###############################################################
#  Generated by:      Cadence Innovus 21.35-s114_1
#  OS:                Linux x86_64(Host ID pc231.ee.hacettepe.edu.tr)
#  Generated on:      Wed Dec 24 11:12:51 2025
#  Design:            core_macro
#  Command:           write_lef_abstract -5.7 outputs/core_macro/core_macro.lef
###############################################################

VERSION 5.7 ;

BUSBITCHARS "[]" ;
DIVIDERCHAR "/" ;

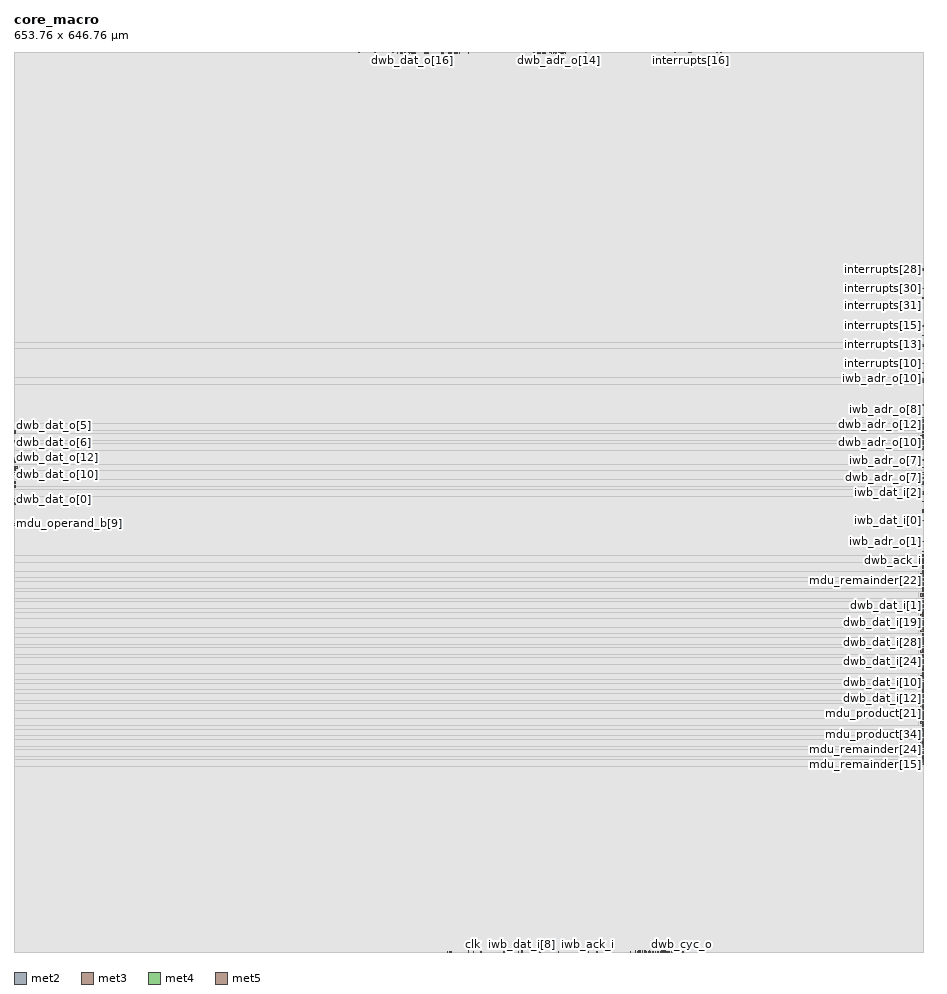
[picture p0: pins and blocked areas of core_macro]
MACRO core_macro
  CLASS BLOCK ;
  SIZE 653.760000 BY 646.760000 ;
  FOREIGN core_macro 0.000000 0.000000 ;
  ORIGIN 0 0 ;
  SYMMETRY X Y R90 ;
  PIN clk
    DIRECTION INPUT ;
    USE SIGNAL ;
    PORT
      LAYER met2 ;
        RECT 329.930000 0.000000 330.070000 0.485000 ;
    END
  END clk
  PIN rst_n
    DIRECTION INPUT ;
    USE SIGNAL ;
    PORT
      LAYER met3 ;
        RECT 652.960000 380.250000 653.760000 380.550000 ;
    END
  END rst_n
  PIN iwb_adr_o[31]
    DIRECTION OUTPUT ;
    USE SIGNAL ;
    PORT
      LAYER met2 ;
        RECT 399.050000 646.275000 399.190000 646.760000 ;
    END
  END iwb_adr_o[31]
  PIN iwb_adr_o[30]
    DIRECTION OUTPUT ;
    USE SIGNAL ;
    PORT
      LAYER met2 ;
        RECT 389.930000 646.275000 390.070000 646.760000 ;
    END
  END iwb_adr_o[30]
  PIN iwb_adr_o[29]
    DIRECTION OUTPUT ;
    USE SIGNAL ;
    PORT
      LAYER met4 ;
        RECT 391.230000 645.960000 391.530000 646.760000 ;
    END
  END iwb_adr_o[29]
  PIN iwb_adr_o[28]
    DIRECTION OUTPUT ;
    USE SIGNAL ;
    PORT
      LAYER met2 ;
        RECT 392.330000 646.275000 392.470000 646.760000 ;
    END
  END iwb_adr_o[28]
  PIN iwb_adr_o[27]
    DIRECTION OUTPUT ;
    USE SIGNAL ;
    PORT
      LAYER met2 ;
        RECT 394.250000 646.275000 394.390000 646.760000 ;
    END
  END iwb_adr_o[27]
  PIN iwb_adr_o[26]
    DIRECTION OUTPUT ;
    USE SIGNAL ;
    PORT
      LAYER met4 ;
        RECT 392.460000 645.960000 392.760000 646.760000 ;
    END
  END iwb_adr_o[26]
  PIN iwb_adr_o[25]
    DIRECTION OUTPUT ;
    USE SIGNAL ;
    PORT
      LAYER met2 ;
        RECT 393.290000 646.275000 393.430000 646.760000 ;
    END
  END iwb_adr_o[25]
  PIN iwb_adr_o[24]
    DIRECTION OUTPUT ;
    USE SIGNAL ;
    PORT
      LAYER met2 ;
        RECT 395.210000 646.275000 395.350000 646.760000 ;
    END
  END iwb_adr_o[24]
  PIN iwb_adr_o[23]
    DIRECTION OUTPUT ;
    USE SIGNAL ;
    PORT
      LAYER met4 ;
        RECT 393.690000 645.960000 393.990000 646.760000 ;
    END
  END iwb_adr_o[23]
  PIN iwb_adr_o[22]
    DIRECTION OUTPUT ;
    USE SIGNAL ;
    PORT
      LAYER met2 ;
        RECT 396.170000 646.275000 396.310000 646.760000 ;
    END
  END iwb_adr_o[22]
  PIN iwb_adr_o[21]
    DIRECTION OUTPUT ;
    USE SIGNAL ;
    PORT
      LAYER met4 ;
        RECT 396.150000 645.960000 396.450000 646.760000 ;
    END
  END iwb_adr_o[21]
  PIN iwb_adr_o[20]
    DIRECTION OUTPUT ;
    USE SIGNAL ;
    PORT
      LAYER met2 ;
        RECT 401.450000 646.275000 401.590000 646.760000 ;
    END
  END iwb_adr_o[20]
  PIN iwb_adr_o[19]
    DIRECTION OUTPUT ;
    USE SIGNAL ;
    PORT
      LAYER met2 ;
        RECT 414.410000 646.275000 414.550000 646.760000 ;
    END
  END iwb_adr_o[19]
  PIN iwb_adr_o[18]
    DIRECTION OUTPUT ;
    USE SIGNAL ;
    PORT
      LAYER met2 ;
        RECT 412.970000 646.275000 413.110000 646.760000 ;
    END
  END iwb_adr_o[18]
  PIN iwb_adr_o[17]
    DIRECTION OUTPUT ;
    USE SIGNAL ;
    PORT
      LAYER met2 ;
        RECT 411.050000 646.275000 411.190000 646.760000 ;
    END
  END iwb_adr_o[17]
  PIN iwb_adr_o[16]
    DIRECTION OUTPUT ;
    USE SIGNAL ;
    PORT
      LAYER met2 ;
        RECT 415.850000 646.275000 415.990000 646.760000 ;
    END
  END iwb_adr_o[16]
  PIN iwb_adr_o[15]
    DIRECTION OUTPUT ;
    USE SIGNAL ;
    PORT
      LAYER met2 ;
        RECT 419.690000 646.275000 419.830000 646.760000 ;
    END
  END iwb_adr_o[15]
  PIN iwb_adr_o[14]
    DIRECTION OUTPUT ;
    USE SIGNAL ;
    PORT
      LAYER met2 ;
        RECT 423.530000 646.275000 423.670000 646.760000 ;
    END
  END iwb_adr_o[14]
  PIN iwb_adr_o[13]
    DIRECTION OUTPUT ;
    USE SIGNAL ;
    PORT
      LAYER met2 ;
        RECT 424.970000 646.275000 425.110000 646.760000 ;
    END
  END iwb_adr_o[13]
  PIN iwb_adr_o[12]
    DIRECTION OUTPUT ;
    USE SIGNAL ;
    PORT
      LAYER met2 ;
        RECT 427.850000 646.275000 427.990000 646.760000 ;
    END
  END iwb_adr_o[12]
  PIN iwb_adr_o[11]
    DIRECTION OUTPUT ;
    USE SIGNAL ;
    PORT
      LAYER met3 ;
        RECT 652.960000 410.750000 653.760000 411.050000 ;
    END
  END iwb_adr_o[11]
  PIN iwb_adr_o[10]
    DIRECTION OUTPUT ;
    USE SIGNAL ;
    PORT
      LAYER met3 ;
        RECT 652.960000 411.970000 653.760000 412.270000 ;
    END
  END iwb_adr_o[10]
  PIN iwb_adr_o[9]
    DIRECTION OUTPUT ;
    USE SIGNAL ;
    PORT
      LAYER met3 ;
        RECT 652.960000 393.060000 653.760000 393.360000 ;
    END
  END iwb_adr_o[9]
  PIN iwb_adr_o[8]
    DIRECTION OUTPUT ;
    USE SIGNAL ;
    PORT
      LAYER met3 ;
        RECT 652.960000 383.910000 653.760000 384.210000 ;
    END
  END iwb_adr_o[8]
  PIN iwb_adr_o[7]
    DIRECTION OUTPUT ;
    USE SIGNAL ;
    PORT
      LAYER met3 ;
        RECT 652.960000 353.410000 653.760000 353.710000 ;
    END
  END iwb_adr_o[7]
  PIN iwb_adr_o[6]
    DIRECTION OUTPUT ;
    USE SIGNAL ;
    PORT
      LAYER met3 ;
        RECT 652.960000 287.530000 653.760000 287.830000 ;
    END
  END iwb_adr_o[6]
  PIN iwb_adr_o[5]
    DIRECTION OUTPUT ;
    USE SIGNAL ;
    PORT
      LAYER met3 ;
        RECT 652.960000 282.650000 653.760000 282.950000 ;
    END
  END iwb_adr_o[5]
  PIN iwb_adr_o[4]
    DIRECTION OUTPUT ;
    USE SIGNAL ;
    PORT
      LAYER met3 ;
        RECT 652.960000 272.890000 653.760000 273.190000 ;
    END
  END iwb_adr_o[4]
  PIN iwb_adr_o[3]
    DIRECTION OUTPUT ;
    USE SIGNAL ;
    PORT
      LAYER met3 ;
        RECT 652.960000 271.670000 653.760000 271.970000 ;
    END
  END iwb_adr_o[3]
  PIN iwb_adr_o[2]
    DIRECTION OUTPUT ;
    USE SIGNAL ;
    PORT
      LAYER met3 ;
        RECT 652.960000 275.330000 653.760000 275.630000 ;
    END
  END iwb_adr_o[2]
  PIN iwb_adr_o[1]
    DIRECTION OUTPUT ;
    USE SIGNAL ;
    PORT
      LAYER met3 ;
        RECT 652.960000 294.850000 653.760000 295.150000 ;
    END
  END iwb_adr_o[1]
  PIN iwb_adr_o[0]
    DIRECTION OUTPUT ;
    USE SIGNAL ;
    PORT
      LAYER met5 ;
        RECT 651.260000 281.390000 653.760000 282.990000 ;
    END
  END iwb_adr_o[0]
  PIN iwb_dat_i[31]
    DIRECTION INPUT ;
    USE SIGNAL ;
    PORT
      LAYER met4 ;
        RECT 378.315000 645.960000 378.615000 646.760000 ;
    END
  END iwb_dat_i[31]
  PIN iwb_dat_i[30]
    DIRECTION INPUT ;
    USE SIGNAL ;
    PORT
      LAYER met2 ;
        RECT 351.530000 646.275000 351.670000 646.760000 ;
    END
  END iwb_dat_i[30]
  PIN iwb_dat_i[29]
    DIRECTION INPUT ;
    USE SIGNAL ;
    PORT
      LAYER met2 ;
        RECT 364.490000 646.275000 364.630000 646.760000 ;
    END
  END iwb_dat_i[29]
  PIN iwb_dat_i[28]
    DIRECTION INPUT ;
    USE SIGNAL ;
    PORT
      LAYER met2 ;
        RECT 371.210000 646.275000 371.350000 646.760000 ;
    END
  END iwb_dat_i[28]
  PIN iwb_dat_i[27]
    DIRECTION INPUT ;
    USE SIGNAL ;
    PORT
      LAYER met2 ;
        RECT 354.410000 646.275000 354.550000 646.760000 ;
    END
  END iwb_dat_i[27]
  PIN iwb_dat_i[26]
    DIRECTION INPUT ;
    USE SIGNAL ;
    PORT
      LAYER met2 ;
        RECT 348.650000 646.275000 348.790000 646.760000 ;
    END
  END iwb_dat_i[26]
  PIN iwb_dat_i[25]
    DIRECTION INPUT ;
    USE SIGNAL ;
    PORT
      LAYER met2 ;
        RECT 361.130000 646.275000 361.270000 646.760000 ;
    END
  END iwb_dat_i[25]
  PIN iwb_dat_i[24]
    DIRECTION INPUT ;
    USE SIGNAL ;
    PORT
      LAYER met2 ;
        RECT 352.010000 0.000000 352.150000 0.485000 ;
    END
  END iwb_dat_i[24]
  PIN iwb_dat_i[23]
    DIRECTION INPUT ;
    USE SIGNAL ;
    PORT
      LAYER met2 ;
        RECT 357.290000 0.000000 357.430000 0.485000 ;
    END
  END iwb_dat_i[23]
  PIN iwb_dat_i[22]
    DIRECTION INPUT ;
    USE SIGNAL ;
    PORT
      LAYER met2 ;
        RECT 367.370000 646.275000 367.510000 646.760000 ;
    END
  END iwb_dat_i[22]
  PIN iwb_dat_i[21]
    DIRECTION INPUT ;
    USE SIGNAL ;
    PORT
      LAYER met2 ;
        RECT 373.610000 646.275000 373.750000 646.760000 ;
    END
  END iwb_dat_i[21]
  PIN iwb_dat_i[20]
    DIRECTION INPUT ;
    USE SIGNAL ;
    PORT
      LAYER met2 ;
        RECT 358.250000 646.275000 358.390000 646.760000 ;
    END
  END iwb_dat_i[20]
  PIN iwb_dat_i[19]
    DIRECTION INPUT ;
    USE SIGNAL ;
    PORT
      LAYER met2 ;
        RECT 377.450000 0.000000 377.590000 0.485000 ;
    END
  END iwb_dat_i[19]
  PIN iwb_dat_i[18]
    DIRECTION INPUT ;
    USE SIGNAL ;
    PORT
      LAYER met2 ;
        RECT 371.690000 0.000000 371.830000 0.485000 ;
    END
  END iwb_dat_i[18]
  PIN iwb_dat_i[17]
    DIRECTION INPUT ;
    USE SIGNAL ;
    PORT
      LAYER met2 ;
        RECT 391.370000 0.000000 391.510000 0.485000 ;
    END
  END iwb_dat_i[17]
  PIN iwb_dat_i[16]
    DIRECTION INPUT ;
    USE SIGNAL ;
    PORT
      LAYER met2 ;
        RECT 378.410000 0.000000 378.550000 0.485000 ;
    END
  END iwb_dat_i[16]
  PIN iwb_dat_i[15]
    DIRECTION INPUT ;
    USE SIGNAL ;
    PORT
      LAYER met2 ;
        RECT 364.490000 0.000000 364.630000 0.485000 ;
    END
  END iwb_dat_i[15]
  PIN iwb_dat_i[14]
    DIRECTION INPUT ;
    USE SIGNAL ;
    PORT
      LAYER met2 ;
        RECT 385.130000 646.275000 385.270000 646.760000 ;
    END
  END iwb_dat_i[14]
  PIN iwb_dat_i[13]
    DIRECTION INPUT ;
    USE SIGNAL ;
    PORT
      LAYER met4 ;
        RECT 394.920000 645.960000 395.220000 646.760000 ;
    END
  END iwb_dat_i[13]
  PIN iwb_dat_i[12]
    DIRECTION INPUT ;
    USE SIGNAL ;
    PORT
      LAYER met2 ;
        RECT 397.130000 646.275000 397.270000 646.760000 ;
    END
  END iwb_dat_i[12]
  PIN iwb_dat_i[11]
    DIRECTION INPUT ;
    USE SIGNAL ;
    PORT
      LAYER met2 ;
        RECT 362.570000 0.000000 362.710000 0.485000 ;
    END
  END iwb_dat_i[11]
  PIN iwb_dat_i[10]
    DIRECTION INPUT ;
    USE SIGNAL ;
    PORT
      LAYER met2 ;
        RECT 358.250000 0.000000 358.390000 0.485000 ;
    END
  END iwb_dat_i[10]
  PIN iwb_dat_i[9]
    DIRECTION INPUT ;
    USE SIGNAL ;
    PORT
      LAYER met2 ;
        RECT 355.850000 0.000000 355.990000 0.485000 ;
    END
  END iwb_dat_i[9]
  PIN iwb_dat_i[8]
    DIRECTION INPUT ;
    USE SIGNAL ;
    PORT
      LAYER met4 ;
        RECT 364.785000 0.000000 365.085000 0.800000 ;
    END
  END iwb_dat_i[8]
  PIN iwb_dat_i[7]
    DIRECTION INPUT ;
    USE SIGNAL ;
    PORT
      LAYER met3 ;
        RECT 652.960000 343.040000 653.760000 343.340000 ;
    END
  END iwb_dat_i[7]
  PIN iwb_dat_i[6]
    DIRECTION INPUT ;
    USE SIGNAL ;
    PORT
      LAYER met5 ;
        RECT 651.260000 328.970000 653.760000 330.570000 ;
    END
  END iwb_dat_i[6]
  PIN iwb_dat_i[5]
    DIRECTION INPUT ;
    USE SIGNAL ;
    PORT
      LAYER met3 ;
        RECT 652.960000 344.260000 653.760000 344.560000 ;
    END
  END iwb_dat_i[5]
  PIN iwb_dat_i[4]
    DIRECTION INPUT ;
    USE SIGNAL ;
    PORT
      LAYER met3 ;
        RECT 652.960000 323.520000 653.760000 323.820000 ;
    END
  END iwb_dat_i[4]
  PIN iwb_dat_i[3]
    DIRECTION INPUT ;
    USE SIGNAL ;
    PORT
      LAYER met5 ;
        RECT 651.260000 336.290000 653.760000 337.890000 ;
    END
  END iwb_dat_i[3]
  PIN iwb_dat_i[2]
    DIRECTION INPUT ;
    USE SIGNAL ;
    PORT
      LAYER met3 ;
        RECT 652.960000 335.720000 653.760000 336.020000 ;
    END
  END iwb_dat_i[2]
  PIN iwb_dat_i[1]
    DIRECTION INPUT ;
    USE SIGNAL ;
    PORT
      LAYER met3 ;
        RECT 652.960000 315.590000 653.760000 315.890000 ;
    END
  END iwb_dat_i[1]
  PIN iwb_dat_i[0]
    DIRECTION INPUT ;
    USE SIGNAL ;
    PORT
      LAYER met3 ;
        RECT 652.960000 310.100000 653.760000 310.400000 ;
    END
  END iwb_dat_i[0]
  PIN iwb_cyc_o
    DIRECTION OUTPUT ;
    USE SIGNAL ;
    PORT
      LAYER met2 ;
        RECT 418.250000 0.000000 418.390000 0.485000 ;
    END
  END iwb_cyc_o
  PIN iwb_stb_o
    DIRECTION OUTPUT ;
    USE SIGNAL ;
    PORT
      LAYER met2 ;
        RECT 419.210000 0.000000 419.350000 0.485000 ;
    END
  END iwb_stb_o
  PIN iwb_ack_i
    DIRECTION INPUT ;
    USE SIGNAL ;
    PORT
      LAYER met2 ;
        RECT 412.490000 0.000000 412.630000 0.485000 ;
    END
  END iwb_ack_i
  PIN dwb_adr_o[31]
    DIRECTION OUTPUT ;
    USE SIGNAL ;
    PORT
      LAYER met2 ;
        RECT 376.010000 646.275000 376.150000 646.760000 ;
    END
  END dwb_adr_o[31]
  PIN dwb_adr_o[30]
    DIRECTION OUTPUT ;
    USE SIGNAL ;
    PORT
      LAYER met2 ;
        RECT 378.890000 646.275000 379.030000 646.760000 ;
    END
  END dwb_adr_o[30]
  PIN dwb_adr_o[29]
    DIRECTION OUTPUT ;
    USE SIGNAL ;
    PORT
      LAYER met4 ;
        RECT 375.855000 645.960000 376.155000 646.760000 ;
    END
  END dwb_adr_o[29]
  PIN dwb_adr_o[28]
    DIRECTION OUTPUT ;
    USE SIGNAL ;
    PORT
      LAYER met2 ;
        RECT 379.850000 646.275000 379.990000 646.760000 ;
    END
  END dwb_adr_o[28]
  PIN dwb_adr_o[27]
    DIRECTION OUTPUT ;
    USE SIGNAL ;
    PORT
      LAYER met2 ;
        RECT 376.970000 646.275000 377.110000 646.760000 ;
    END
  END dwb_adr_o[27]
  PIN dwb_adr_o[26]
    DIRECTION OUTPUT ;
    USE SIGNAL ;
    PORT
      LAYER met4 ;
        RECT 379.545000 645.960000 379.845000 646.760000 ;
    END
  END dwb_adr_o[26]
  PIN dwb_adr_o[25]
    DIRECTION OUTPUT ;
    USE SIGNAL ;
    PORT
      LAYER met2 ;
        RECT 380.810000 646.275000 380.950000 646.760000 ;
    END
  END dwb_adr_o[25]
  PIN dwb_adr_o[24]
    DIRECTION OUTPUT ;
    USE SIGNAL ;
    PORT
      LAYER met2 ;
        RECT 381.770000 646.275000 381.910000 646.760000 ;
    END
  END dwb_adr_o[24]
  PIN dwb_adr_o[23]
    DIRECTION OUTPUT ;
    USE SIGNAL ;
    PORT
      LAYER met4 ;
        RECT 380.775000 645.960000 381.075000 646.760000 ;
    END
  END dwb_adr_o[23]
  PIN dwb_adr_o[22]
    DIRECTION OUTPUT ;
    USE SIGNAL ;
    PORT
      LAYER met4 ;
        RECT 377.085000 645.960000 377.385000 646.760000 ;
    END
  END dwb_adr_o[22]
  PIN dwb_adr_o[21]
    DIRECTION OUTPUT ;
    USE SIGNAL ;
    PORT
      LAYER met4 ;
        RECT 382.005000 645.960000 382.305000 646.760000 ;
    END
  END dwb_adr_o[21]
  PIN dwb_adr_o[20]
    DIRECTION OUTPUT ;
    USE SIGNAL ;
    PORT
      LAYER met2 ;
        RECT 386.090000 646.275000 386.230000 646.760000 ;
    END
  END dwb_adr_o[20]
  PIN dwb_adr_o[19]
    DIRECTION OUTPUT ;
    USE SIGNAL ;
    PORT
      LAYER met2 ;
        RECT 388.970000 646.275000 389.110000 646.760000 ;
    END
  END dwb_adr_o[19]
  PIN dwb_adr_o[18]
    DIRECTION OUTPUT ;
    USE SIGNAL ;
    PORT
      LAYER met4 ;
        RECT 389.385000 645.960000 389.685000 646.760000 ;
    END
  END dwb_adr_o[18]
  PIN dwb_adr_o[17]
    DIRECTION OUTPUT ;
    USE SIGNAL ;
    PORT
      LAYER met4 ;
        RECT 386.310000 645.960000 386.610000 646.760000 ;
    END
  END dwb_adr_o[17]
  PIN dwb_adr_o[16]
    DIRECTION OUTPUT ;
    USE SIGNAL ;
    PORT
      LAYER met2 ;
        RECT 387.050000 646.275000 387.190000 646.760000 ;
    END
  END dwb_adr_o[16]
  PIN dwb_adr_o[15]
    DIRECTION OUTPUT ;
    USE SIGNAL ;
    PORT
      LAYER met2 ;
        RECT 388.010000 646.275000 388.150000 646.760000 ;
    END
  END dwb_adr_o[15]
  PIN dwb_adr_o[14]
    DIRECTION OUTPUT ;
    USE SIGNAL ;
    PORT
      LAYER met2 ;
        RECT 391.370000 646.275000 391.510000 646.760000 ;
    END
  END dwb_adr_o[14]
  PIN dwb_adr_o[13]
    DIRECTION OUTPUT ;
    USE SIGNAL ;
    PORT
      LAYER met3 ;
        RECT 652.960000 381.470000 653.760000 381.770000 ;
    END
  END dwb_adr_o[13]
  PIN dwb_adr_o[12]
    DIRECTION OUTPUT ;
    USE SIGNAL ;
    PORT
      LAYER met3 ;
        RECT 652.960000 373.540000 653.760000 373.840000 ;
    END
  END dwb_adr_o[12]
  PIN dwb_adr_o[11]
    DIRECTION OUTPUT ;
    USE SIGNAL ;
    PORT
      LAYER met3 ;
        RECT 652.960000 382.690000 653.760000 382.990000 ;
    END
  END dwb_adr_o[11]
  PIN dwb_adr_o[10]
    DIRECTION OUTPUT ;
    USE SIGNAL ;
    PORT
      LAYER met3 ;
        RECT 652.960000 366.220000 653.760000 366.520000 ;
    END
  END dwb_adr_o[10]
  PIN dwb_adr_o[9]
    DIRECTION OUTPUT ;
    USE SIGNAL ;
    PORT
      LAYER met3 ;
        RECT 652.960000 371.710000 653.760000 372.010000 ;
    END
  END dwb_adr_o[9]
  PIN dwb_adr_o[8]
    DIRECTION OUTPUT ;
    USE SIGNAL ;
    PORT
      LAYER met4 ;
        RECT 387.540000 645.960000 387.840000 646.760000 ;
    END
  END dwb_adr_o[8]
  PIN dwb_adr_o[7]
    DIRECTION OUTPUT ;
    USE SIGNAL ;
    PORT
      LAYER met3 ;
        RECT 652.960000 340.600000 653.760000 340.900000 ;
    END
  END dwb_adr_o[7]
  PIN dwb_adr_o[6]
    DIRECTION OUTPUT ;
    USE SIGNAL ;
    PORT
      LAYER met3 ;
        RECT 652.960000 318.030000 653.760000 318.330000 ;
    END
  END dwb_adr_o[6]
  PIN dwb_adr_o[5]
    DIRECTION OUTPUT ;
    USE SIGNAL ;
    PORT
      LAYER met3 ;
        RECT 652.960000 336.940000 653.760000 337.240000 ;
    END
  END dwb_adr_o[5]
  PIN dwb_adr_o[4]
    DIRECTION OUTPUT ;
    USE SIGNAL ;
    PORT
      LAYER met3 ;
        RECT 652.960000 316.810000 653.760000 317.110000 ;
    END
  END dwb_adr_o[4]
  PIN dwb_adr_o[3]
    DIRECTION OUTPUT ;
    USE SIGNAL ;
    PORT
      LAYER met3 ;
        RECT 652.960000 329.010000 653.760000 329.310000 ;
    END
  END dwb_adr_o[3]
  PIN dwb_adr_o[2]
    DIRECTION OUTPUT ;
    USE SIGNAL ;
    PORT
      LAYER met3 ;
        RECT 652.960000 347.920000 653.760000 348.220000 ;
    END
  END dwb_adr_o[2]
  PIN dwb_adr_o[1]
    DIRECTION OUTPUT ;
    USE SIGNAL ;
    PORT
      LAYER met3 ;
        RECT 652.960000 361.340000 653.760000 361.640000 ;
    END
  END dwb_adr_o[1]
  PIN dwb_adr_o[0]
    DIRECTION OUTPUT ;
    USE SIGNAL ;
    PORT
      LAYER met3 ;
        RECT 652.960000 363.170000 653.760000 363.470000 ;
    END
  END dwb_adr_o[0]
  PIN dwb_dat_o[31]
    DIRECTION OUTPUT ;
    USE SIGNAL ;
    PORT
      LAYER met3 ;
        RECT 0.000000 348.530000 0.800000 348.830000 ;
    END
  END dwb_dat_o[31]
  PIN dwb_dat_o[30]
    DIRECTION OUTPUT ;
    USE SIGNAL ;
    PORT
      LAYER met2 ;
        RECT 243.050000 646.275000 243.190000 646.760000 ;
    END
  END dwb_dat_o[30]
  PIN dwb_dat_o[29]
    DIRECTION OUTPUT ;
    USE SIGNAL ;
    PORT
      LAYER met2 ;
        RECT 247.850000 646.275000 247.990000 646.760000 ;
    END
  END dwb_dat_o[29]
  PIN dwb_dat_o[28]
    DIRECTION OUTPUT ;
    USE SIGNAL ;
    PORT
      LAYER met2 ;
        RECT 272.330000 646.275000 272.470000 646.760000 ;
    END
  END dwb_dat_o[28]
  PIN dwb_dat_o[27]
    DIRECTION OUTPUT ;
    USE SIGNAL ;
    PORT
      LAYER met2 ;
        RECT 279.050000 646.275000 279.190000 646.760000 ;
    END
  END dwb_dat_o[27]
  PIN dwb_dat_o[26]
    DIRECTION OUTPUT ;
    USE SIGNAL ;
    PORT
      LAYER met2 ;
        RECT 282.890000 646.275000 283.030000 646.760000 ;
    END
  END dwb_dat_o[26]
  PIN dwb_dat_o[25]
    DIRECTION OUTPUT ;
    USE SIGNAL ;
    PORT
      LAYER met2 ;
        RECT 258.410000 646.275000 258.550000 646.760000 ;
    END
  END dwb_dat_o[25]
  PIN dwb_dat_o[24]
    DIRECTION OUTPUT ;
    USE SIGNAL ;
    PORT
      LAYER met2 ;
        RECT 296.330000 646.275000 296.470000 646.760000 ;
    END
  END dwb_dat_o[24]
  PIN dwb_dat_o[23]
    DIRECTION OUTPUT ;
    USE SIGNAL ;
    PORT
      LAYER met2 ;
        RECT 318.410000 646.275000 318.550000 646.760000 ;
    END
  END dwb_dat_o[23]
  PIN dwb_dat_o[22]
    DIRECTION OUTPUT ;
    USE SIGNAL ;
    PORT
      LAYER met2 ;
        RECT 322.730000 646.275000 322.870000 646.760000 ;
    END
  END dwb_dat_o[22]
  PIN dwb_dat_o[21]
    DIRECTION OUTPUT ;
    USE SIGNAL ;
    PORT
      LAYER met3 ;
        RECT 0.000000 351.580000 0.800000 351.880000 ;
    END
  END dwb_dat_o[21]
  PIN dwb_dat_o[20]
    DIRECTION OUTPUT ;
    USE SIGNAL ;
    PORT
      LAYER met2 ;
        RECT 316.490000 646.275000 316.630000 646.760000 ;
    END
  END dwb_dat_o[20]
  PIN dwb_dat_o[19]
    DIRECTION OUTPUT ;
    USE SIGNAL ;
    PORT
      LAYER met2 ;
        RECT 274.730000 646.275000 274.870000 646.760000 ;
    END
  END dwb_dat_o[19]
  PIN dwb_dat_o[18]
    DIRECTION OUTPUT ;
    USE SIGNAL ;
    PORT
      LAYER met2 ;
        RECT 311.690000 646.275000 311.830000 646.760000 ;
    END
  END dwb_dat_o[18]
  PIN dwb_dat_o[17]
    DIRECTION OUTPUT ;
    USE SIGNAL ;
    PORT
      LAYER met4 ;
        RECT 285.450000 645.960000 285.750000 646.760000 ;
    END
  END dwb_dat_o[17]
  PIN dwb_dat_o[16]
    DIRECTION OUTPUT ;
    USE SIGNAL ;
    PORT
      LAYER met2 ;
        RECT 286.250000 646.275000 286.390000 646.760000 ;
    END
  END dwb_dat_o[16]
  PIN dwb_dat_o[15]
    DIRECTION OUTPUT ;
    USE SIGNAL ;
    PORT
      LAYER met4 ;
        RECT 287.910000 645.960000 288.210000 646.760000 ;
    END
  END dwb_dat_o[15]
  PIN dwb_dat_o[14]
    DIRECTION OUTPUT ;
    USE SIGNAL ;
    PORT
      LAYER met2 ;
        RECT 336.170000 0.000000 336.310000 0.485000 ;
    END
  END dwb_dat_o[14]
  PIN dwb_dat_o[13]
    DIRECTION OUTPUT ;
    USE SIGNAL ;
    PORT
      LAYER met2 ;
        RECT 313.610000 0.000000 313.750000 0.485000 ;
    END
  END dwb_dat_o[13]
  PIN dwb_dat_o[12]
    DIRECTION OUTPUT ;
    USE SIGNAL ;
    PORT
      LAYER met3 ;
        RECT 0.000000 355.240000 0.800000 355.540000 ;
    END
  END dwb_dat_o[12]
  PIN dwb_dat_o[11]
    DIRECTION OUTPUT ;
    USE SIGNAL ;
    PORT
      LAYER met3 ;
        RECT 0.000000 346.090000 0.800000 346.390000 ;
    END
  END dwb_dat_o[11]
  PIN dwb_dat_o[10]
    DIRECTION OUTPUT ;
    USE SIGNAL ;
    PORT
      LAYER met3 ;
        RECT 0.000000 343.040000 0.800000 343.340000 ;
    END
  END dwb_dat_o[10]
  PIN dwb_dat_o[9]
    DIRECTION OUTPUT ;
    USE SIGNAL ;
    PORT
      LAYER met3 ;
        RECT 0.000000 306.440000 0.800000 306.740000 ;
    END
  END dwb_dat_o[9]
  PIN dwb_dat_o[8]
    DIRECTION OUTPUT ;
    USE SIGNAL ;
    PORT
      LAYER met2 ;
        RECT 251.210000 646.275000 251.350000 646.760000 ;
    END
  END dwb_dat_o[8]
  PIN dwb_dat_o[7]
    DIRECTION OUTPUT ;
    USE SIGNAL ;
    PORT
      LAYER met3 ;
        RECT 0.000000 336.330000 0.800000 336.630000 ;
    END
  END dwb_dat_o[7]
  PIN dwb_dat_o[6]
    DIRECTION OUTPUT ;
    USE SIGNAL ;
    PORT
      LAYER met3 ;
        RECT 0.000000 366.220000 0.800000 366.520000 ;
    END
  END dwb_dat_o[6]
  PIN dwb_dat_o[5]
    DIRECTION OUTPUT ;
    USE SIGNAL ;
    PORT
      LAYER met3 ;
        RECT 0.000000 372.930000 0.800000 373.230000 ;
    END
  END dwb_dat_o[5]
  PIN dwb_dat_o[4]
    DIRECTION OUTPUT ;
    USE SIGNAL ;
    PORT
      LAYER met2 ;
        RECT 307.370000 646.275000 307.510000 646.760000 ;
    END
  END dwb_dat_o[4]
  PIN dwb_dat_o[3]
    DIRECTION OUTPUT ;
    USE SIGNAL ;
    PORT
      LAYER met3 ;
        RECT 0.000000 333.890000 0.800000 334.190000 ;
    END
  END dwb_dat_o[3]
  PIN dwb_dat_o[2]
    DIRECTION OUTPUT ;
    USE SIGNAL ;
    PORT
      LAYER met2 ;
        RECT 311.690000 0.000000 311.830000 0.485000 ;
    END
  END dwb_dat_o[2]
  PIN dwb_dat_o[1]
    DIRECTION OUTPUT ;
    USE SIGNAL ;
    PORT
      LAYER met3 ;
        RECT 0.000000 322.910000 0.800000 323.210000 ;
    END
  END dwb_dat_o[1]
  PIN dwb_dat_o[0]
    DIRECTION OUTPUT ;
    USE SIGNAL ;
    PORT
      LAYER met3 ;
        RECT 0.000000 325.350000 0.800000 325.650000 ;
    END
  END dwb_dat_o[0]
  PIN dwb_dat_i[31]
    DIRECTION INPUT ;
    USE SIGNAL ;
    PORT
      LAYER met3 ;
        RECT 652.960000 189.930000 653.760000 190.230000 ;
    END
  END dwb_dat_i[31]
  PIN dwb_dat_i[30]
    DIRECTION INPUT ;
    USE SIGNAL ;
    PORT
      LAYER met3 ;
        RECT 652.960000 210.060000 653.760000 210.360000 ;
    END
  END dwb_dat_i[30]
  PIN dwb_dat_i[29]
    DIRECTION INPUT ;
    USE SIGNAL ;
    PORT
      LAYER met3 ;
        RECT 652.960000 256.420000 653.760000 256.720000 ;
    END
  END dwb_dat_i[29]
  PIN dwb_dat_i[28]
    DIRECTION INPUT ;
    USE SIGNAL ;
    PORT
      LAYER met3 ;
        RECT 652.960000 216.770000 653.760000 217.070000 ;
    END
  END dwb_dat_i[28]
  PIN dwb_dat_i[27]
    DIRECTION INPUT ;
    USE SIGNAL ;
    PORT
      LAYER met5 ;
        RECT 651.260000 189.890000 653.760000 191.490000 ;
    END
  END dwb_dat_i[27]
  PIN dwb_dat_i[26]
    DIRECTION INPUT ;
    USE SIGNAL ;
    PORT
      LAYER met5 ;
        RECT 651.260000 215.510000 653.760000 217.110000 ;
    END
  END dwb_dat_i[26]
  PIN dwb_dat_i[25]
    DIRECTION INPUT ;
    USE SIGNAL ;
    PORT
      LAYER met3 ;
        RECT 652.960000 223.480000 653.760000 223.780000 ;
    END
  END dwb_dat_i[25]
  PIN dwb_dat_i[24]
    DIRECTION INPUT ;
    USE SIGNAL ;
    PORT
      LAYER met3 ;
        RECT 652.960000 208.840000 653.760000 209.140000 ;
    END
  END dwb_dat_i[24]
  PIN dwb_dat_i[23]
    DIRECTION INPUT ;
    USE SIGNAL ;
    PORT
      LAYER met3 ;
        RECT 652.960000 249.710000 653.760000 250.010000 ;
    END
  END dwb_dat_i[23]
  PIN dwb_dat_i[22]
    DIRECTION INPUT ;
    USE SIGNAL ;
    PORT
      LAYER met5 ;
        RECT 651.260000 248.450000 653.760000 250.050000 ;
    END
  END dwb_dat_i[22]
  PIN dwb_dat_i[21]
    DIRECTION INPUT ;
    USE SIGNAL ;
    PORT
      LAYER met3 ;
        RECT 652.960000 196.640000 653.760000 196.940000 ;
    END
  END dwb_dat_i[21]
  PIN dwb_dat_i[20]
    DIRECTION INPUT ;
    USE SIGNAL ;
    PORT
      LAYER met3 ;
        RECT 652.960000 191.150000 653.760000 191.450000 ;
    END
  END dwb_dat_i[20]
  PIN dwb_dat_i[19]
    DIRECTION INPUT ;
    USE SIGNAL ;
    PORT
      LAYER met3 ;
        RECT 652.960000 236.900000 653.760000 237.200000 ;
    END
  END dwb_dat_i[19]
  PIN dwb_dat_i[18]
    DIRECTION INPUT ;
    USE SIGNAL ;
    PORT
      LAYER met5 ;
        RECT 651.260000 255.770000 653.760000 257.370000 ;
    END
  END dwb_dat_i[18]
  PIN dwb_dat_i[17]
    DIRECTION INPUT ;
    USE SIGNAL ;
    PORT
      LAYER met3 ;
        RECT 652.960000 257.640000 653.760000 257.940000 ;
    END
  END dwb_dat_i[17]
  PIN dwb_dat_i[16]
    DIRECTION INPUT ;
    USE SIGNAL ;
    PORT
      LAYER met5 ;
        RECT 651.260000 222.830000 653.760000 224.430000 ;
    END
  END dwb_dat_i[16]
  PIN dwb_dat_i[15]
    DIRECTION INPUT ;
    USE SIGNAL ;
    PORT
      LAYER met3 ;
        RECT 652.960000 230.190000 653.760000 230.490000 ;
    END
  END dwb_dat_i[15]
  PIN dwb_dat_i[14]
    DIRECTION INPUT ;
    USE SIGNAL ;
    PORT
      LAYER met3 ;
        RECT 652.960000 188.710000 653.760000 189.010000 ;
    END
  END dwb_dat_i[14]
  PIN dwb_dat_i[13]
    DIRECTION INPUT ;
    USE SIGNAL ;
    PORT
      LAYER met3 ;
        RECT 652.960000 192.370000 653.760000 192.670000 ;
    END
  END dwb_dat_i[13]
  PIN dwb_dat_i[12]
    DIRECTION INPUT ;
    USE SIGNAL ;
    PORT
      LAYER met3 ;
        RECT 652.960000 187.490000 653.760000 187.790000 ;
    END
  END dwb_dat_i[12]
  PIN dwb_dat_i[11]
    DIRECTION INPUT ;
    USE SIGNAL ;
    PORT
      LAYER met3 ;
        RECT 652.960000 197.860000 653.760000 198.160000 ;
    END
  END dwb_dat_i[11]
  PIN dwb_dat_i[10]
    DIRECTION INPUT ;
    USE SIGNAL ;
    PORT
      LAYER met3 ;
        RECT 652.960000 193.590000 653.760000 193.890000 ;
    END
  END dwb_dat_i[10]
  PIN dwb_dat_i[9]
    DIRECTION INPUT ;
    USE SIGNAL ;
    PORT
      LAYER met5 ;
        RECT 651.260000 197.210000 653.760000 198.810000 ;
    END
  END dwb_dat_i[9]
  PIN dwb_dat_i[8]
    DIRECTION INPUT ;
    USE SIGNAL ;
    PORT
      LAYER met3 ;
        RECT 652.960000 203.350000 653.760000 203.650000 ;
    END
  END dwb_dat_i[8]
  PIN dwb_dat_i[7]
    DIRECTION INPUT ;
    USE SIGNAL ;
    PORT
      LAYER met3 ;
        RECT 652.960000 186.270000 653.760000 186.570000 ;
    END
  END dwb_dat_i[7]
  PIN dwb_dat_i[6]
    DIRECTION INPUT ;
    USE SIGNAL ;
    PORT
      LAYER met3 ;
        RECT 652.960000 194.810000 653.760000 195.110000 ;
    END
  END dwb_dat_i[6]
  PIN dwb_dat_i[5]
    DIRECTION INPUT ;
    USE SIGNAL ;
    PORT
      LAYER met3 ;
        RECT 652.960000 185.050000 653.760000 185.350000 ;
    END
  END dwb_dat_i[5]
  PIN dwb_dat_i[4]
    DIRECTION INPUT ;
    USE SIGNAL ;
    PORT
      LAYER met3 ;
        RECT 652.960000 183.830000 653.760000 184.130000 ;
    END
  END dwb_dat_i[4]
  PIN dwb_dat_i[3]
    DIRECTION INPUT ;
    USE SIGNAL ;
    PORT
      LAYER met3 ;
        RECT 652.960000 202.130000 653.760000 202.430000 ;
    END
  END dwb_dat_i[3]
  PIN dwb_dat_i[2]
    DIRECTION INPUT ;
    USE SIGNAL ;
    PORT
      LAYER met3 ;
        RECT 652.960000 204.570000 653.760000 204.870000 ;
    END
  END dwb_dat_i[2]
  PIN dwb_dat_i[1]
    DIRECTION INPUT ;
    USE SIGNAL ;
    PORT
      LAYER met3 ;
        RECT 652.960000 243.610000 653.760000 243.910000 ;
    END
  END dwb_dat_i[1]
  PIN dwb_dat_i[0]
    DIRECTION INPUT ;
    USE SIGNAL ;
    PORT
      LAYER met3 ;
        RECT 652.960000 242.390000 653.760000 242.690000 ;
    END
  END dwb_dat_i[0]
  PIN dwb_we_o
    DIRECTION OUTPUT ;
    USE SIGNAL ;
    PORT
      LAYER met3 ;
        RECT 652.960000 365.000000 653.760000 365.300000 ;
    END
  END dwb_we_o
  PIN dwb_sel_o[3]
    DIRECTION OUTPUT ;
    USE SIGNAL ;
    PORT
      LAYER met2 ;
        RECT 326.570000 646.275000 326.710000 646.760000 ;
    END
  END dwb_sel_o[3]
  PIN dwb_sel_o[2]
    DIRECTION OUTPUT ;
    USE SIGNAL ;
    PORT
      LAYER met4 ;
        RECT 326.655000 645.960000 326.955000 646.760000 ;
    END
  END dwb_sel_o[2]
  PIN dwb_sel_o[1]
    DIRECTION OUTPUT ;
    USE SIGNAL ;
    PORT
      LAYER met2 ;
        RECT 326.570000 0.000000 326.710000 0.485000 ;
    END
  END dwb_sel_o[1]
  PIN dwb_sel_o[0]
    DIRECTION OUTPUT ;
    USE SIGNAL ;
    PORT
      LAYER met4 ;
        RECT 326.655000 0.000000 326.955000 0.800000 ;
    END
  END dwb_sel_o[0]
  PIN dwb_cyc_o
    DIRECTION OUTPUT ;
    USE SIGNAL ;
    PORT
      LAYER met2 ;
        RECT 480.170000 0.000000 480.310000 0.485000 ;
    END
  END dwb_cyc_o
  PIN dwb_stb_o
    DIRECTION OUTPUT ;
    USE SIGNAL ;
    PORT
      LAYER met2 ;
        RECT 481.130000 0.000000 481.270000 0.485000 ;
    END
  END dwb_stb_o
  PIN dwb_ack_i
    DIRECTION INPUT ;
    USE SIGNAL ;
    PORT
      LAYER met3 ;
        RECT 652.960000 281.430000 653.760000 281.730000 ;
    END
  END dwb_ack_i
  PIN dwb_err_i
    DIRECTION INPUT ;
    USE SIGNAL ;
    PORT
      LAYER met3 ;
        RECT 652.960000 367.440000 653.760000 367.740000 ;
    END
  END dwb_err_i
  PIN mdu_start
    DIRECTION OUTPUT ;
    USE SIGNAL ;
    PORT
      LAYER met3 ;
        RECT 652.960000 283.870000 653.760000 284.170000 ;
    END
  END mdu_start
  PIN mdu_ack
    DIRECTION OUTPUT ;
    USE SIGNAL ;
    PORT
      LAYER met5 ;
        RECT 651.260000 134.990000 653.760000 136.590000 ;
    END
  END mdu_ack
  PIN mdu_funct3[2]
    DIRECTION OUTPUT ;
    USE SIGNAL ;
    PORT
      LAYER met3 ;
        RECT 652.960000 228.360000 653.760000 228.660000 ;
    END
  END mdu_funct3[2]
  PIN mdu_funct3[1]
    DIRECTION OUTPUT ;
    USE SIGNAL ;
    PORT
      LAYER met3 ;
        RECT 652.960000 232.020000 653.760000 232.320000 ;
    END
  END mdu_funct3[1]
  PIN mdu_funct3[0]
    DIRECTION OUTPUT ;
    USE SIGNAL ;
    PORT
      LAYER met5 ;
        RECT 651.260000 230.150000 653.760000 231.750000 ;
    END
  END mdu_funct3[0]
  PIN mdu_operand_a[31]
    DIRECTION OUTPUT ;
    USE SIGNAL ;
    PORT
      LAYER met4 ;
        RECT 275.610000 645.960000 275.910000 646.760000 ;
    END
  END mdu_operand_a[31]
  PIN mdu_operand_a[30]
    DIRECTION OUTPUT ;
    USE SIGNAL ;
    PORT
      LAYER met2 ;
        RECT 289.610000 646.275000 289.750000 646.760000 ;
    END
  END mdu_operand_a[30]
  PIN mdu_operand_a[29]
    DIRECTION OUTPUT ;
    USE SIGNAL ;
    PORT
      LAYER met2 ;
        RECT 287.210000 646.275000 287.350000 646.760000 ;
    END
  END mdu_operand_a[29]
  PIN mdu_operand_a[28]
    DIRECTION OUTPUT ;
    USE SIGNAL ;
    PORT
      LAYER met4 ;
        RECT 296.520000 645.960000 296.820000 646.760000 ;
    END
  END mdu_operand_a[28]
  PIN mdu_operand_a[27]
    DIRECTION OUTPUT ;
    USE SIGNAL ;
    PORT
      LAYER met2 ;
        RECT 292.970000 646.275000 293.110000 646.760000 ;
    END
  END mdu_operand_a[27]
  PIN mdu_operand_a[26]
    DIRECTION OUTPUT ;
    USE SIGNAL ;
    PORT
      LAYER met2 ;
        RECT 304.010000 646.275000 304.150000 646.760000 ;
    END
  END mdu_operand_a[26]
  PIN mdu_operand_a[25]
    DIRECTION OUTPUT ;
    USE SIGNAL ;
    PORT
      LAYER met2 ;
        RECT 302.570000 646.275000 302.710000 646.760000 ;
    END
  END mdu_operand_a[25]
  PIN mdu_operand_a[24]
    DIRECTION OUTPUT ;
    USE SIGNAL ;
    PORT
      LAYER met4 ;
        RECT 306.975000 645.960000 307.275000 646.760000 ;
    END
  END mdu_operand_a[24]
  PIN mdu_operand_a[23]
    DIRECTION OUTPUT ;
    USE SIGNAL ;
    PORT
      LAYER met2 ;
        RECT 313.130000 646.275000 313.270000 646.760000 ;
    END
  END mdu_operand_a[23]
  PIN mdu_operand_a[22]
    DIRECTION OUTPUT ;
    USE SIGNAL ;
    PORT
      LAYER met4 ;
        RECT 316.200000 645.960000 316.500000 646.760000 ;
    END
  END mdu_operand_a[22]
  PIN mdu_operand_a[21]
    DIRECTION OUTPUT ;
    USE SIGNAL ;
    PORT
      LAYER met2 ;
        RECT 314.570000 646.275000 314.710000 646.760000 ;
    END
  END mdu_operand_a[21]
  PIN mdu_operand_a[20]
    DIRECTION OUTPUT ;
    USE SIGNAL ;
    PORT
      LAYER met4 ;
        RECT 314.355000 645.960000 314.655000 646.760000 ;
    END
  END mdu_operand_a[20]
  PIN mdu_operand_a[19]
    DIRECTION OUTPUT ;
    USE SIGNAL ;
    PORT
      LAYER met4 ;
        RECT 313.125000 645.960000 313.425000 646.760000 ;
    END
  END mdu_operand_a[19]
  PIN mdu_operand_a[18]
    DIRECTION OUTPUT ;
    USE SIGNAL ;
    PORT
      LAYER met4 ;
        RECT 317.430000 645.960000 317.730000 646.760000 ;
    END
  END mdu_operand_a[18]
  PIN mdu_operand_a[17]
    DIRECTION OUTPUT ;
    USE SIGNAL ;
    PORT
      LAYER met4 ;
        RECT 311.895000 645.960000 312.195000 646.760000 ;
    END
  END mdu_operand_a[17]
  PIN mdu_operand_a[16]
    DIRECTION OUTPUT ;
    USE SIGNAL ;
    PORT
      LAYER met2 ;
        RECT 315.530000 646.275000 315.670000 646.760000 ;
    END
  END mdu_operand_a[16]
  PIN mdu_operand_a[15]
    DIRECTION OUTPUT ;
    USE SIGNAL ;
    PORT
      LAYER met4 ;
        RECT 318.660000 645.960000 318.960000 646.760000 ;
    END
  END mdu_operand_a[15]
  PIN mdu_operand_a[14]
    DIRECTION OUTPUT ;
    USE SIGNAL ;
    PORT
      LAYER met4 ;
        RECT 319.890000 645.960000 320.190000 646.760000 ;
    END
  END mdu_operand_a[14]
  PIN mdu_operand_a[13]
    DIRECTION OUTPUT ;
    USE SIGNAL ;
    PORT
      LAYER met2 ;
        RECT 320.330000 646.275000 320.470000 646.760000 ;
    END
  END mdu_operand_a[13]
  PIN mdu_operand_a[12]
    DIRECTION OUTPUT ;
    USE SIGNAL ;
    PORT
      LAYER met4 ;
        RECT 308.205000 645.960000 308.505000 646.760000 ;
    END
  END mdu_operand_a[12]
  PIN mdu_operand_a[11]
    DIRECTION OUTPUT ;
    USE SIGNAL ;
    PORT
      LAYER met2 ;
        RECT 309.290000 646.275000 309.430000 646.760000 ;
    END
  END mdu_operand_a[11]
  PIN mdu_operand_a[10]
    DIRECTION OUTPUT ;
    USE SIGNAL ;
    PORT
      LAYER met2 ;
        RECT 306.410000 646.275000 306.550000 646.760000 ;
    END
  END mdu_operand_a[10]
  PIN mdu_operand_a[9]
    DIRECTION OUTPUT ;
    USE SIGNAL ;
    PORT
      LAYER met4 ;
        RECT 297.750000 645.960000 298.050000 646.760000 ;
    END
  END mdu_operand_a[9]
  PIN mdu_operand_a[8]
    DIRECTION OUTPUT ;
    USE SIGNAL ;
    PORT
      LAYER met2 ;
        RECT 295.370000 646.275000 295.510000 646.760000 ;
    END
  END mdu_operand_a[8]
  PIN mdu_operand_a[7]
    DIRECTION OUTPUT ;
    USE SIGNAL ;
    PORT
      LAYER met4 ;
        RECT 280.530000 645.960000 280.830000 646.760000 ;
    END
  END mdu_operand_a[7]
  PIN mdu_operand_a[6]
    DIRECTION OUTPUT ;
    USE SIGNAL ;
    PORT
      LAYER met4 ;
        RECT 295.290000 645.960000 295.590000 646.760000 ;
    END
  END mdu_operand_a[6]
  PIN mdu_operand_a[5]
    DIRECTION OUTPUT ;
    USE SIGNAL ;
    PORT
      LAYER met2 ;
        RECT 280.970000 646.275000 281.110000 646.760000 ;
    END
  END mdu_operand_a[5]
  PIN mdu_operand_a[4]
    DIRECTION OUTPUT ;
    USE SIGNAL ;
    PORT
      LAYER met2 ;
        RECT 278.090000 646.275000 278.230000 646.760000 ;
    END
  END mdu_operand_a[4]
  PIN mdu_operand_a[3]
    DIRECTION OUTPUT ;
    USE SIGNAL ;
    PORT
      LAYER met4 ;
        RECT 277.455000 645.960000 277.755000 646.760000 ;
    END
  END mdu_operand_a[3]
  PIN mdu_operand_a[2]
    DIRECTION OUTPUT ;
    USE SIGNAL ;
    PORT
      LAYER met4 ;
        RECT 278.685000 645.960000 278.985000 646.760000 ;
    END
  END mdu_operand_a[2]
  PIN mdu_operand_a[1]
    DIRECTION OUTPUT ;
    USE SIGNAL ;
    PORT
      LAYER met2 ;
        RECT 281.930000 646.275000 282.070000 646.760000 ;
    END
  END mdu_operand_a[1]
  PIN mdu_operand_a[0]
    DIRECTION OUTPUT ;
    USE SIGNAL ;
    PORT
      LAYER met2 ;
        RECT 300.170000 646.275000 300.310000 646.760000 ;
    END
  END mdu_operand_a[0]
  PIN mdu_operand_b[31]
    DIRECTION OUTPUT ;
    USE SIGNAL ;
    PORT
      LAYER met3 ;
        RECT 0.000000 347.310000 0.800000 347.610000 ;
    END
  END mdu_operand_b[31]
  PIN mdu_operand_b[30]
    DIRECTION OUTPUT ;
    USE SIGNAL ;
    PORT
      LAYER met2 ;
        RECT 244.010000 646.275000 244.150000 646.760000 ;
    END
  END mdu_operand_b[30]
  PIN mdu_operand_b[29]
    DIRECTION OUTPUT ;
    USE SIGNAL ;
    PORT
      LAYER met2 ;
        RECT 248.810000 646.275000 248.950000 646.760000 ;
    END
  END mdu_operand_b[29]
  PIN mdu_operand_b[28]
    DIRECTION OUTPUT ;
    USE SIGNAL ;
    PORT
      LAYER met2 ;
        RECT 271.370000 646.275000 271.510000 646.760000 ;
    END
  END mdu_operand_b[28]
  PIN mdu_operand_b[27]
    DIRECTION OUTPUT ;
    USE SIGNAL ;
    PORT
      LAYER met2 ;
        RECT 280.010000 646.275000 280.150000 646.760000 ;
    END
  END mdu_operand_b[27]
  PIN mdu_operand_b[26]
    DIRECTION OUTPUT ;
    USE SIGNAL ;
    PORT
      LAYER met2 ;
        RECT 283.850000 646.275000 283.990000 646.760000 ;
    END
  END mdu_operand_b[26]
  PIN mdu_operand_b[25]
    DIRECTION OUTPUT ;
    USE SIGNAL ;
    PORT
      LAYER met2 ;
        RECT 259.370000 646.275000 259.510000 646.760000 ;
    END
  END mdu_operand_b[25]
  PIN mdu_operand_b[24]
    DIRECTION OUTPUT ;
    USE SIGNAL ;
    PORT
      LAYER met2 ;
        RECT 297.290000 646.275000 297.430000 646.760000 ;
    END
  END mdu_operand_b[24]
  PIN mdu_operand_b[23]
    DIRECTION OUTPUT ;
    USE SIGNAL ;
    PORT
      LAYER met2 ;
        RECT 319.370000 646.275000 319.510000 646.760000 ;
    END
  END mdu_operand_b[23]
  PIN mdu_operand_b[22]
    DIRECTION OUTPUT ;
    USE SIGNAL ;
    PORT
      LAYER met2 ;
        RECT 321.770000 646.275000 321.910000 646.760000 ;
    END
  END mdu_operand_b[22]
  PIN mdu_operand_b[21]
    DIRECTION OUTPUT ;
    USE SIGNAL ;
    PORT
      LAYER met3 ;
        RECT 0.000000 352.800000 0.800000 353.100000 ;
    END
  END mdu_operand_b[21]
  PIN mdu_operand_b[20]
    DIRECTION OUTPUT ;
    USE SIGNAL ;
    PORT
      LAYER met2 ;
        RECT 317.450000 646.275000 317.590000 646.760000 ;
    END
  END mdu_operand_b[20]
  PIN mdu_operand_b[19]
    DIRECTION OUTPUT ;
    USE SIGNAL ;
    PORT
      LAYER met2 ;
        RECT 275.690000 646.275000 275.830000 646.760000 ;
    END
  END mdu_operand_b[19]
  PIN mdu_operand_b[18]
    DIRECTION OUTPUT ;
    USE SIGNAL ;
    PORT
      LAYER met2 ;
        RECT 310.730000 646.275000 310.870000 646.760000 ;
    END
  END mdu_operand_b[18]
  PIN mdu_operand_b[17]
    DIRECTION OUTPUT ;
    USE SIGNAL ;
    PORT
      LAYER met4 ;
        RECT 284.220000 645.960000 284.520000 646.760000 ;
    END
  END mdu_operand_b[17]
  PIN mdu_operand_b[16]
    DIRECTION OUTPUT ;
    USE SIGNAL ;
    PORT
      LAYER met2 ;
        RECT 285.290000 646.275000 285.430000 646.760000 ;
    END
  END mdu_operand_b[16]
  PIN mdu_operand_b[15]
    DIRECTION OUTPUT ;
    USE SIGNAL ;
    PORT
      LAYER met4 ;
        RECT 286.680000 645.960000 286.980000 646.760000 ;
    END
  END mdu_operand_b[15]
  PIN mdu_operand_b[14]
    DIRECTION OUTPUT ;
    USE SIGNAL ;
    PORT
      LAYER met2 ;
        RECT 335.210000 0.000000 335.350000 0.485000 ;
    END
  END mdu_operand_b[14]
  PIN mdu_operand_b[13]
    DIRECTION OUTPUT ;
    USE SIGNAL ;
    PORT
      LAYER met2 ;
        RECT 314.570000 0.000000 314.710000 0.485000 ;
    END
  END mdu_operand_b[13]
  PIN mdu_operand_b[12]
    DIRECTION OUTPUT ;
    USE SIGNAL ;
    PORT
      LAYER met3 ;
        RECT 0.000000 354.020000 0.800000 354.320000 ;
    END
  END mdu_operand_b[12]
  PIN mdu_operand_b[11]
    DIRECTION OUTPUT ;
    USE SIGNAL ;
    PORT
      LAYER met5 ;
        RECT 0.000000 347.270000 2.500000 348.870000 ;
    END
  END mdu_operand_b[11]
  PIN mdu_operand_b[10]
    DIRECTION OUTPUT ;
    USE SIGNAL ;
    PORT
      LAYER met3 ;
        RECT 0.000000 344.260000 0.800000 344.560000 ;
    END
  END mdu_operand_b[10]
  PIN mdu_operand_b[9]
    DIRECTION OUTPUT ;
    USE SIGNAL ;
    PORT
      LAYER met3 ;
        RECT 0.000000 307.660000 0.800000 307.960000 ;
    END
  END mdu_operand_b[9]
  PIN mdu_operand_b[8]
    DIRECTION OUTPUT ;
    USE SIGNAL ;
    PORT
      LAYER met2 ;
        RECT 250.250000 646.275000 250.390000 646.760000 ;
    END
  END mdu_operand_b[8]
  PIN mdu_operand_b[7]
    DIRECTION OUTPUT ;
    USE SIGNAL ;
    PORT
      LAYER met3 ;
        RECT 0.000000 337.550000 0.800000 337.850000 ;
    END
  END mdu_operand_b[7]
  PIN mdu_operand_b[6]
    DIRECTION OUTPUT ;
    USE SIGNAL ;
    PORT
      LAYER met3 ;
        RECT 0.000000 367.440000 0.800000 367.740000 ;
    END
  END mdu_operand_b[6]
  PIN mdu_operand_b[5]
    DIRECTION OUTPUT ;
    USE SIGNAL ;
    PORT
      LAYER met3 ;
        RECT 0.000000 374.150000 0.800000 374.450000 ;
    END
  END mdu_operand_b[5]
  PIN mdu_operand_b[4]
    DIRECTION OUTPUT ;
    USE SIGNAL ;
    PORT
      LAYER met2 ;
        RECT 308.330000 646.275000 308.470000 646.760000 ;
    END
  END mdu_operand_b[4]
  PIN mdu_operand_b[3]
    DIRECTION OUTPUT ;
    USE SIGNAL ;
    PORT
      LAYER met3 ;
        RECT 0.000000 335.110000 0.800000 335.410000 ;
    END
  END mdu_operand_b[3]
  PIN mdu_operand_b[2]
    DIRECTION OUTPUT ;
    USE SIGNAL ;
    PORT
      LAYER met2 ;
        RECT 312.650000 0.000000 312.790000 0.485000 ;
    END
  END mdu_operand_b[2]
  PIN mdu_operand_b[1]
    DIRECTION OUTPUT ;
    USE SIGNAL ;
    PORT
      LAYER met3 ;
        RECT 0.000000 321.690000 0.800000 321.990000 ;
    END
  END mdu_operand_b[1]
  PIN mdu_operand_b[0]
    DIRECTION OUTPUT ;
    USE SIGNAL ;
    PORT
      LAYER met3 ;
        RECT 0.000000 324.130000 0.800000 324.430000 ;
    END
  END mdu_operand_b[0]
  PIN mdu_busy
    DIRECTION INPUT ;
    USE SIGNAL ;
    PORT
      LAYER met2 ;
        RECT 327.530000 646.275000 327.670000 646.760000 ;
    END
  END mdu_busy
  PIN mdu_done
    DIRECTION INPUT ;
    USE SIGNAL ;
    PORT
      LAYER met3 ;
        RECT 652.960000 285.090000 653.760000 285.390000 ;
    END
  END mdu_done
  PIN mdu_product[63]
    DIRECTION INPUT ;
    USE SIGNAL ;
    PORT
      LAYER met5 ;
        RECT 651.260000 182.570000 653.760000 184.170000 ;
    END
  END mdu_product[63]
  PIN mdu_product[62]
    DIRECTION INPUT ;
    USE SIGNAL ;
    PORT
      LAYER met3 ;
        RECT 652.960000 182.610000 653.760000 182.910000 ;
    END
  END mdu_product[62]
  PIN mdu_product[61]
    DIRECTION INPUT ;
    USE SIGNAL ;
    PORT
      LAYER met3 ;
        RECT 652.960000 263.130000 653.760000 263.430000 ;
    END
  END mdu_product[61]
  PIN mdu_product[60]
    DIRECTION INPUT ;
    USE SIGNAL ;
    PORT
      LAYER met3 ;
        RECT 652.960000 150.280000 653.760000 150.580000 ;
    END
  END mdu_product[60]
  PIN mdu_product[59]
    DIRECTION INPUT ;
    USE SIGNAL ;
    PORT
      LAYER met3 ;
        RECT 652.960000 199.080000 653.760000 199.380000 ;
    END
  END mdu_product[59]
  PIN mdu_product[58]
    DIRECTION INPUT ;
    USE SIGNAL ;
    PORT
      LAYER met3 ;
        RECT 652.960000 215.550000 653.760000 215.850000 ;
    END
  END mdu_product[58]
  PIN mdu_product[57]
    DIRECTION INPUT ;
    USE SIGNAL ;
    PORT
      LAYER met3 ;
        RECT 652.960000 169.800000 653.760000 170.100000 ;
    END
  END mdu_product[57]
  PIN mdu_product[56]
    DIRECTION INPUT ;
    USE SIGNAL ;
    PORT
      LAYER met3 ;
        RECT 652.960000 143.570000 653.760000 143.870000 ;
    END
  END mdu_product[56]
  PIN mdu_product[55]
    DIRECTION INPUT ;
    USE SIGNAL ;
    PORT
      LAYER met3 ;
        RECT 652.960000 250.930000 653.760000 251.230000 ;
    END
  END mdu_product[55]
  PIN mdu_product[54]
    DIRECTION INPUT ;
    USE SIGNAL ;
    PORT
      LAYER met3 ;
        RECT 652.960000 269.840000 653.760000 270.140000 ;
    END
  END mdu_product[54]
  PIN mdu_product[53]
    DIRECTION INPUT ;
    USE SIGNAL ;
    PORT
      LAYER met3 ;
        RECT 652.960000 176.510000 653.760000 176.810000 ;
    END
  END mdu_product[53]
  PIN mdu_product[52]
    DIRECTION INPUT ;
    USE SIGNAL ;
    PORT
      LAYER met5 ;
        RECT 651.260000 175.250000 653.760000 176.850000 ;
    END
  END mdu_product[52]
  PIN mdu_product[51]
    DIRECTION INPUT ;
    USE SIGNAL ;
    PORT
      LAYER met3 ;
        RECT 652.960000 222.260000 653.760000 222.560000 ;
    END
  END mdu_product[51]
  PIN mdu_product[50]
    DIRECTION INPUT ;
    USE SIGNAL ;
    PORT
      LAYER met5 ;
        RECT 651.260000 270.410000 653.760000 272.010000 ;
    END
  END mdu_product[50]
  PIN mdu_product[49]
    DIRECTION INPUT ;
    USE SIGNAL ;
    PORT
      LAYER met3 ;
        RECT 652.960000 244.830000 653.760000 245.130000 ;
    END
  END mdu_product[49]
  PIN mdu_product[48]
    DIRECTION INPUT ;
    USE SIGNAL ;
    PORT
      LAYER met3 ;
        RECT 652.960000 163.090000 653.760000 163.390000 ;
    END
  END mdu_product[48]
  PIN mdu_product[47]
    DIRECTION INPUT ;
    USE SIGNAL ;
    PORT
      LAYER met3 ;
        RECT 652.960000 156.990000 653.760000 157.290000 ;
    END
  END mdu_product[47]
  PIN mdu_product[46]
    DIRECTION INPUT ;
    USE SIGNAL ;
    PORT
      LAYER met2 ;
        RECT 468.170000 0.000000 468.310000 0.485000 ;
    END
  END mdu_product[46]
  PIN mdu_product[45]
    DIRECTION INPUT ;
    USE SIGNAL ;
    PORT
      LAYER met2 ;
        RECT 474.410000 0.000000 474.550000 0.485000 ;
    END
  END mdu_product[45]
  PIN mdu_product[44]
    DIRECTION INPUT ;
    USE SIGNAL ;
    PORT
      LAYER met2 ;
        RECT 443.210000 0.000000 443.350000 0.485000 ;
    END
  END mdu_product[44]
  PIN mdu_product[43]
    DIRECTION INPUT ;
    USE SIGNAL ;
    PORT
      LAYER met2 ;
        RECT 446.570000 0.000000 446.710000 0.485000 ;
    END
  END mdu_product[43]
  PIN mdu_product[42]
    DIRECTION INPUT ;
    USE SIGNAL ;
    PORT
      LAYER met4 ;
        RECT 468.105000 0.000000 468.405000 0.800000 ;
    END
  END mdu_product[42]
  PIN mdu_product[41]
    DIRECTION INPUT ;
    USE SIGNAL ;
    PORT
      LAYER met2 ;
        RECT 455.690000 0.000000 455.830000 0.485000 ;
    END
  END mdu_product[41]
  PIN mdu_product[40]
    DIRECTION INPUT ;
    USE SIGNAL ;
    PORT
      LAYER met4 ;
        RECT 446.580000 0.000000 446.880000 0.800000 ;
    END
  END mdu_product[40]
  PIN mdu_product[39]
    DIRECTION INPUT ;
    USE SIGNAL ;
    PORT
      LAYER met3 ;
        RECT 652.960000 177.730000 653.760000 178.030000 ;
    END
  END mdu_product[39]
  PIN mdu_product[38]
    DIRECTION INPUT ;
    USE SIGNAL ;
    PORT
      LAYER met3 ;
        RECT 652.960000 164.310000 653.760000 164.610000 ;
    END
  END mdu_product[38]
  PIN mdu_product[37]
    DIRECTION INPUT ;
    USE SIGNAL ;
    PORT
      LAYER met2 ;
        RECT 458.570000 0.000000 458.710000 0.485000 ;
    END
  END mdu_product[37]
  PIN mdu_product[36]
    DIRECTION INPUT ;
    USE SIGNAL ;
    PORT
      LAYER met2 ;
        RECT 462.410000 0.000000 462.550000 0.485000 ;
    END
  END mdu_product[36]
  PIN mdu_product[35]
    DIRECTION INPUT ;
    USE SIGNAL ;
    PORT
      LAYER met5 ;
        RECT 651.260000 208.190000 653.760000 209.790000 ;
    END
  END mdu_product[35]
  PIN mdu_product[34]
    DIRECTION INPUT ;
    USE SIGNAL ;
    PORT
      LAYER met3 ;
        RECT 652.960000 161.870000 653.760000 162.170000 ;
    END
  END mdu_product[34]
  PIN mdu_product[33]
    DIRECTION INPUT ;
    USE SIGNAL ;
    PORT
      LAYER met3 ;
        RECT 652.960000 235.680000 653.760000 235.980000 ;
    END
  END mdu_product[33]
  PIN mdu_product[32]
    DIRECTION INPUT ;
    USE SIGNAL ;
    PORT
      LAYER met3 ;
        RECT 652.960000 227.140000 653.760000 227.440000 ;
    END
  END mdu_product[32]
  PIN mdu_product[31]
    DIRECTION INPUT ;
    USE SIGNAL ;
    PORT
      LAYER met3 ;
        RECT 652.960000 200.300000 653.760000 200.600000 ;
    END
  END mdu_product[31]
  PIN mdu_product[30]
    DIRECTION INPUT ;
    USE SIGNAL ;
    PORT
      LAYER met3 ;
        RECT 652.960000 181.390000 653.760000 181.690000 ;
    END
  END mdu_product[30]
  PIN mdu_product[29]
    DIRECTION INPUT ;
    USE SIGNAL ;
    PORT
      LAYER met3 ;
        RECT 652.960000 255.200000 653.760000 255.500000 ;
    END
  END mdu_product[29]
  PIN mdu_product[28]
    DIRECTION INPUT ;
    USE SIGNAL ;
    PORT
      LAYER met5 ;
        RECT 651.260000 164.270000 653.760000 165.870000 ;
    END
  END mdu_product[28]
  PIN mdu_product[27]
    DIRECTION INPUT ;
    USE SIGNAL ;
    PORT
      LAYER met3 ;
        RECT 652.960000 205.790000 653.760000 206.090000 ;
    END
  END mdu_product[27]
  PIN mdu_product[26]
    DIRECTION INPUT ;
    USE SIGNAL ;
    PORT
      LAYER met3 ;
        RECT 652.960000 217.990000 653.760000 218.290000 ;
    END
  END mdu_product[26]
  PIN mdu_product[25]
    DIRECTION INPUT ;
    USE SIGNAL ;
    PORT
      LAYER met3 ;
        RECT 652.960000 180.170000 653.760000 180.470000 ;
    END
  END mdu_product[25]
  PIN mdu_product[24]
    DIRECTION INPUT ;
    USE SIGNAL ;
    PORT
      LAYER met5 ;
        RECT 651.260000 149.630000 653.760000 151.230000 ;
    END
  END mdu_product[24]
  PIN mdu_product[23]
    DIRECTION INPUT ;
    USE SIGNAL ;
    PORT
      LAYER met3 ;
        RECT 652.960000 238.120000 653.760000 238.420000 ;
    END
  END mdu_product[23]
  PIN mdu_product[22]
    DIRECTION INPUT ;
    USE SIGNAL ;
    PORT
      LAYER met3 ;
        RECT 652.960000 258.860000 653.760000 259.160000 ;
    END
  END mdu_product[22]
  PIN mdu_product[21]
    DIRECTION INPUT ;
    USE SIGNAL ;
    PORT
      LAYER met3 ;
        RECT 652.960000 171.020000 653.760000 171.320000 ;
    END
  END mdu_product[21]
  PIN mdu_product[20]
    DIRECTION INPUT ;
    USE SIGNAL ;
    PORT
      LAYER met3 ;
        RECT 652.960000 175.290000 653.760000 175.590000 ;
    END
  END mdu_product[20]
  PIN mdu_product[19]
    DIRECTION INPUT ;
    USE SIGNAL ;
    PORT
      LAYER met3 ;
        RECT 652.960000 224.700000 653.760000 225.000000 ;
    END
  END mdu_product[19]
  PIN mdu_product[18]
    DIRECTION INPUT ;
    USE SIGNAL ;
    PORT
      LAYER met3 ;
        RECT 652.960000 253.980000 653.760000 254.280000 ;
    END
  END mdu_product[18]
  PIN mdu_product[17]
    DIRECTION INPUT ;
    USE SIGNAL ;
    PORT
      LAYER met5 ;
        RECT 651.260000 241.130000 653.760000 242.730000 ;
    END
  END mdu_product[17]
  PIN mdu_product[16]
    DIRECTION INPUT ;
    USE SIGNAL ;
    PORT
      LAYER met3 ;
        RECT 652.960000 178.950000 653.760000 179.250000 ;
    END
  END mdu_product[16]
  PIN mdu_product[15]
    DIRECTION INPUT ;
    USE SIGNAL ;
    PORT
      LAYER met3 ;
        RECT 652.960000 165.530000 653.760000 165.830000 ;
    END
  END mdu_product[15]
  PIN mdu_product[14]
    DIRECTION INPUT ;
    USE SIGNAL ;
    PORT
      LAYER met2 ;
        RECT 466.730000 0.000000 466.870000 0.485000 ;
    END
  END mdu_product[14]
  PIN mdu_product[13]
    DIRECTION INPUT ;
    USE SIGNAL ;
    PORT
      LAYER met2 ;
        RECT 478.250000 0.000000 478.390000 0.485000 ;
    END
  END mdu_product[13]
  PIN mdu_product[12]
    DIRECTION INPUT ;
    USE SIGNAL ;
    PORT
      LAYER met2 ;
        RECT 449.930000 0.000000 450.070000 0.485000 ;
    END
  END mdu_product[12]
  PIN mdu_product[11]
    DIRECTION INPUT ;
    USE SIGNAL ;
    PORT
      LAYER met2 ;
        RECT 453.290000 0.000000 453.430000 0.485000 ;
    END
  END mdu_product[11]
  PIN mdu_product[10]
    DIRECTION INPUT ;
    USE SIGNAL ;
    PORT
      LAYER met2 ;
        RECT 465.770000 0.000000 465.910000 0.485000 ;
    END
  END mdu_product[10]
  PIN mdu_product[9]
    DIRECTION INPUT ;
    USE SIGNAL ;
    PORT
      LAYER met2 ;
        RECT 456.650000 0.000000 456.790000 0.485000 ;
    END
  END mdu_product[9]
  PIN mdu_product[8]
    DIRECTION INPUT ;
    USE SIGNAL ;
    PORT
      LAYER met4 ;
        RECT 450.270000 0.000000 450.570000 0.800000 ;
    END
  END mdu_product[8]
  PIN mdu_product[7]
    DIRECTION INPUT ;
    USE SIGNAL ;
    PORT
      LAYER met3 ;
        RECT 652.960000 168.580000 653.760000 168.880000 ;
    END
  END mdu_product[7]
  PIN mdu_product[6]
    DIRECTION INPUT ;
    USE SIGNAL ;
    PORT
      LAYER met3 ;
        RECT 652.960000 172.240000 653.760000 172.540000 ;
    END
  END mdu_product[6]
  PIN mdu_product[5]
    DIRECTION INPUT ;
    USE SIGNAL ;
    PORT
      LAYER met4 ;
        RECT 456.420000 0.000000 456.720000 0.800000 ;
    END
  END mdu_product[5]
  PIN mdu_product[4]
    DIRECTION INPUT ;
    USE SIGNAL ;
    PORT
      LAYER met4 ;
        RECT 465.645000 0.000000 465.945000 0.800000 ;
    END
  END mdu_product[4]
  PIN mdu_product[3]
    DIRECTION INPUT ;
    USE SIGNAL ;
    PORT
      LAYER met3 ;
        RECT 652.960000 211.280000 653.760000 211.580000 ;
    END
  END mdu_product[3]
  PIN mdu_product[2]
    DIRECTION INPUT ;
    USE SIGNAL ;
    PORT
      LAYER met2 ;
        RECT 475.850000 0.000000 475.990000 0.485000 ;
    END
  END mdu_product[2]
  PIN mdu_product[1]
    DIRECTION INPUT ;
    USE SIGNAL ;
    PORT
      LAYER met3 ;
        RECT 652.960000 233.240000 653.760000 233.540000 ;
    END
  END mdu_product[1]
  PIN mdu_product[0]
    DIRECTION INPUT ;
    USE SIGNAL ;
    PORT
      LAYER met3 ;
        RECT 652.960000 225.920000 653.760000 226.220000 ;
    END
  END mdu_product[0]
  PIN mdu_quotient[31]
    DIRECTION INPUT ;
    USE SIGNAL ;
    PORT
      LAYER met3 ;
        RECT 652.960000 174.070000 653.760000 174.370000 ;
    END
  END mdu_quotient[31]
  PIN mdu_quotient[30]
    DIRECTION INPUT ;
    USE SIGNAL ;
    PORT
      LAYER met3 ;
        RECT 652.960000 207.010000 653.760000 207.310000 ;
    END
  END mdu_quotient[30]
  PIN mdu_quotient[29]
    DIRECTION INPUT ;
    USE SIGNAL ;
    PORT
      LAYER met3 ;
        RECT 652.960000 241.170000 653.760000 241.470000 ;
    END
  END mdu_quotient[29]
  PIN mdu_quotient[28]
    DIRECTION INPUT ;
    USE SIGNAL ;
    PORT
      LAYER met5 ;
        RECT 651.260000 156.950000 653.760000 158.550000 ;
    END
  END mdu_quotient[28]
  PIN mdu_quotient[27]
    DIRECTION INPUT ;
    USE SIGNAL ;
    PORT
      LAYER met3 ;
        RECT 652.960000 212.500000 653.760000 212.800000 ;
    END
  END mdu_quotient[27]
  PIN mdu_quotient[26]
    DIRECTION INPUT ;
    USE SIGNAL ;
    PORT
      LAYER met3 ;
        RECT 652.960000 219.210000 653.760000 219.510000 ;
    END
  END mdu_quotient[26]
  PIN mdu_quotient[25]
    DIRECTION INPUT ;
    USE SIGNAL ;
    PORT
      LAYER met3 ;
        RECT 652.960000 167.360000 653.760000 167.660000 ;
    END
  END mdu_quotient[25]
  PIN mdu_quotient[24]
    DIRECTION INPUT ;
    USE SIGNAL ;
    PORT
      LAYER met3 ;
        RECT 652.960000 160.650000 653.760000 160.950000 ;
    END
  END mdu_quotient[24]
  PIN mdu_quotient[23]
    DIRECTION INPUT ;
    USE SIGNAL ;
    PORT
      LAYER met3 ;
        RECT 652.960000 248.490000 653.760000 248.790000 ;
    END
  END mdu_quotient[23]
  PIN mdu_quotient[22]
    DIRECTION INPUT ;
    USE SIGNAL ;
    PORT
      LAYER met3 ;
        RECT 652.960000 246.050000 653.760000 246.350000 ;
    END
  END mdu_quotient[22]
  PIN mdu_quotient[21]
    DIRECTION INPUT ;
    USE SIGNAL ;
    PORT
      LAYER met3 ;
        RECT 652.960000 159.430000 653.760000 159.730000 ;
    END
  END mdu_quotient[21]
  PIN mdu_quotient[20]
    DIRECTION INPUT ;
    USE SIGNAL ;
    PORT
      LAYER met3 ;
        RECT 652.960000 213.720000 653.760000 214.020000 ;
    END
  END mdu_quotient[20]
  PIN mdu_quotient[19]
    DIRECTION INPUT ;
    USE SIGNAL ;
    PORT
      LAYER met3 ;
        RECT 652.960000 221.040000 653.760000 221.340000 ;
    END
  END mdu_quotient[19]
  PIN mdu_quotient[18]
    DIRECTION INPUT ;
    USE SIGNAL ;
    PORT
      LAYER met3 ;
        RECT 652.960000 252.150000 653.760000 252.450000 ;
    END
  END mdu_quotient[18]
  PIN mdu_quotient[17]
    DIRECTION INPUT ;
    USE SIGNAL ;
    PORT
      LAYER met3 ;
        RECT 652.960000 234.460000 653.760000 234.760000 ;
    END
  END mdu_quotient[17]
  PIN mdu_quotient[16]
    DIRECTION INPUT ;
    USE SIGNAL ;
    PORT
      LAYER met3 ;
        RECT 652.960000 158.210000 653.760000 158.510000 ;
    END
  END mdu_quotient[16]
  PIN mdu_quotient[15]
    DIRECTION INPUT ;
    USE SIGNAL ;
    PORT
      LAYER met3 ;
        RECT 652.960000 155.770000 653.760000 156.070000 ;
    END
  END mdu_quotient[15]
  PIN mdu_quotient[14]
    DIRECTION INPUT ;
    USE SIGNAL ;
    PORT
      LAYER met2 ;
        RECT 469.130000 0.000000 469.270000 0.485000 ;
    END
  END mdu_quotient[14]
  PIN mdu_quotient[13]
    DIRECTION INPUT ;
    USE SIGNAL ;
    PORT
      LAYER met2 ;
        RECT 472.490000 0.000000 472.630000 0.485000 ;
    END
  END mdu_quotient[13]
  PIN mdu_quotient[12]
    DIRECTION INPUT ;
    USE SIGNAL ;
    PORT
      LAYER met2 ;
        RECT 448.010000 0.000000 448.150000 0.485000 ;
    END
  END mdu_quotient[12]
  PIN mdu_quotient[11]
    DIRECTION INPUT ;
    USE SIGNAL ;
    PORT
      LAYER met2 ;
        RECT 451.370000 0.000000 451.510000 0.485000 ;
    END
  END mdu_quotient[11]
  PIN mdu_quotient[10]
    DIRECTION INPUT ;
    USE SIGNAL ;
    PORT
      LAYER met2 ;
        RECT 473.450000 0.000000 473.590000 0.485000 ;
    END
  END mdu_quotient[10]
  PIN mdu_quotient[9]
    DIRECTION INPUT ;
    USE SIGNAL ;
    PORT
      LAYER met2 ;
        RECT 457.610000 0.000000 457.750000 0.485000 ;
    END
  END mdu_quotient[9]
  PIN mdu_quotient[8]
    DIRECTION INPUT ;
    USE SIGNAL ;
    PORT
      LAYER met4 ;
        RECT 451.500000 0.000000 451.800000 0.800000 ;
    END
  END mdu_quotient[8]
  PIN mdu_quotient[7]
    DIRECTION INPUT ;
    USE SIGNAL ;
    PORT
      LAYER met3 ;
        RECT 652.960000 154.550000 653.760000 154.850000 ;
    END
  END mdu_quotient[7]
  PIN mdu_quotient[6]
    DIRECTION INPUT ;
    USE SIGNAL ;
    PORT
      LAYER met3 ;
        RECT 652.960000 153.330000 653.760000 153.630000 ;
    END
  END mdu_quotient[6]
  PIN mdu_quotient[5]
    DIRECTION INPUT ;
    USE SIGNAL ;
    PORT
      LAYER met2 ;
        RECT 459.530000 0.000000 459.670000 0.485000 ;
    END
  END mdu_quotient[5]
  PIN mdu_quotient[4]
    DIRECTION INPUT ;
    USE SIGNAL ;
    PORT
      LAYER met2 ;
        RECT 463.370000 0.000000 463.510000 0.485000 ;
    END
  END mdu_quotient[4]
  PIN mdu_quotient[3]
    DIRECTION INPUT ;
    USE SIGNAL ;
    PORT
      LAYER met3 ;
        RECT 652.960000 239.340000 653.760000 239.640000 ;
    END
  END mdu_quotient[3]
  PIN mdu_quotient[2]
    DIRECTION INPUT ;
    USE SIGNAL ;
    PORT
      LAYER met2 ;
        RECT 477.290000 0.000000 477.430000 0.485000 ;
    END
  END mdu_quotient[2]
  PIN mdu_quotient[1]
    DIRECTION INPUT ;
    USE SIGNAL ;
    PORT
      LAYER met3 ;
        RECT 652.960000 247.270000 653.760000 247.570000 ;
    END
  END mdu_quotient[1]
  PIN mdu_quotient[0]
    DIRECTION INPUT ;
    USE SIGNAL ;
    PORT
      LAYER met3 ;
        RECT 652.960000 260.080000 653.760000 260.380000 ;
    END
  END mdu_quotient[0]
  PIN mdu_remainder[31]
    DIRECTION INPUT ;
    USE SIGNAL ;
    PORT
      LAYER met3 ;
        RECT 652.960000 152.110000 653.760000 152.410000 ;
    END
  END mdu_remainder[31]
  PIN mdu_remainder[30]
    DIRECTION INPUT ;
    USE SIGNAL ;
    PORT
      LAYER met3 ;
        RECT 652.960000 149.060000 653.760000 149.360000 ;
    END
  END mdu_remainder[30]
  PIN mdu_remainder[29]
    DIRECTION INPUT ;
    USE SIGNAL ;
    PORT
      LAYER met3 ;
        RECT 652.960000 261.300000 653.760000 261.600000 ;
    END
  END mdu_remainder[29]
  PIN mdu_remainder[28]
    DIRECTION INPUT ;
    USE SIGNAL ;
    PORT
      LAYER met3 ;
        RECT 652.960000 147.840000 653.760000 148.140000 ;
    END
  END mdu_remainder[28]
  PIN mdu_remainder[27]
    DIRECTION INPUT ;
    USE SIGNAL ;
    PORT
      LAYER met5 ;
        RECT 651.260000 263.090000 653.760000 264.690000 ;
    END
  END mdu_remainder[27]
  PIN mdu_remainder[26]
    DIRECTION INPUT ;
    USE SIGNAL ;
    PORT
      LAYER met3 ;
        RECT 652.960000 264.350000 653.760000 264.650000 ;
    END
  END mdu_remainder[26]
  PIN mdu_remainder[25]
    DIRECTION INPUT ;
    USE SIGNAL ;
    PORT
      LAYER met3 ;
        RECT 652.960000 146.620000 653.760000 146.920000 ;
    END
  END mdu_remainder[25]
  PIN mdu_remainder[24]
    DIRECTION INPUT ;
    USE SIGNAL ;
    PORT
      LAYER met3 ;
        RECT 652.960000 145.400000 653.760000 145.700000 ;
    END
  END mdu_remainder[24]
  PIN mdu_remainder[23]
    DIRECTION INPUT ;
    USE SIGNAL ;
    PORT
      LAYER met3 ;
        RECT 652.960000 265.570000 653.760000 265.870000 ;
    END
  END mdu_remainder[23]
  PIN mdu_remainder[22]
    DIRECTION INPUT ;
    USE SIGNAL ;
    PORT
      LAYER met3 ;
        RECT 652.960000 266.790000 653.760000 267.090000 ;
    END
  END mdu_remainder[22]
  PIN mdu_remainder[21]
    DIRECTION INPUT ;
    USE SIGNAL ;
    PORT
      LAYER met5 ;
        RECT 651.260000 142.310000 653.760000 143.910000 ;
    END
  END mdu_remainder[21]
  PIN mdu_remainder[20]
    DIRECTION INPUT ;
    USE SIGNAL ;
    PORT
      LAYER met3 ;
        RECT 652.960000 142.350000 653.760000 142.650000 ;
    END
  END mdu_remainder[20]
  PIN mdu_remainder[19]
    DIRECTION INPUT ;
    USE SIGNAL ;
    PORT
      LAYER met3 ;
        RECT 652.960000 268.010000 653.760000 268.310000 ;
    END
  END mdu_remainder[19]
  PIN mdu_remainder[18]
    DIRECTION INPUT ;
    USE SIGNAL ;
    PORT
      LAYER met3 ;
        RECT 652.960000 274.110000 653.760000 274.410000 ;
    END
  END mdu_remainder[18]
  PIN mdu_remainder[17]
    DIRECTION INPUT ;
    USE SIGNAL ;
    PORT
      LAYER met3 ;
        RECT 652.960000 276.550000 653.760000 276.850000 ;
    END
  END mdu_remainder[17]
  PIN mdu_remainder[16]
    DIRECTION INPUT ;
    USE SIGNAL ;
    PORT
      LAYER met3 ;
        RECT 652.960000 141.130000 653.760000 141.430000 ;
    END
  END mdu_remainder[16]
  PIN mdu_remainder[15]
    DIRECTION INPUT ;
    USE SIGNAL ;
    PORT
      LAYER met3 ;
        RECT 652.960000 139.910000 653.760000 140.210000 ;
    END
  END mdu_remainder[15]
  PIN mdu_remainder[14]
    DIRECTION INPUT ;
    USE SIGNAL ;
    PORT
      LAYER met2 ;
        RECT 470.570000 0.000000 470.710000 0.485000 ;
    END
  END mdu_remainder[14]
  PIN mdu_remainder[13]
    DIRECTION INPUT ;
    USE SIGNAL ;
    PORT
      LAYER met4 ;
        RECT 473.640000 0.000000 473.940000 0.800000 ;
    END
  END mdu_remainder[13]
  PIN mdu_remainder[12]
    DIRECTION INPUT ;
    USE SIGNAL ;
    PORT
      LAYER met2 ;
        RECT 448.970000 0.000000 449.110000 0.485000 ;
    END
  END mdu_remainder[12]
  PIN mdu_remainder[11]
    DIRECTION INPUT ;
    USE SIGNAL ;
    PORT
      LAYER met2 ;
        RECT 454.730000 0.000000 454.870000 0.485000 ;
    END
  END mdu_remainder[11]
  PIN mdu_remainder[10]
    DIRECTION INPUT ;
    USE SIGNAL ;
    PORT
      LAYER met4 ;
        RECT 466.875000 0.000000 467.175000 0.800000 ;
    END
  END mdu_remainder[10]
  PIN mdu_remainder[9]
    DIRECTION INPUT ;
    USE SIGNAL ;
    PORT
      LAYER met4 ;
        RECT 453.345000 0.000000 453.645000 0.800000 ;
    END
  END mdu_remainder[9]
  PIN mdu_remainder[8]
    DIRECTION INPUT ;
    USE SIGNAL ;
    PORT
      LAYER met4 ;
        RECT 449.040000 0.000000 449.340000 0.800000 ;
    END
  END mdu_remainder[8]
  PIN mdu_remainder[7]
    DIRECTION INPUT ;
    USE SIGNAL ;
    PORT
      LAYER met3 ;
        RECT 652.960000 138.690000 653.760000 138.990000 ;
    END
  END mdu_remainder[7]
  PIN mdu_remainder[6]
    DIRECTION INPUT ;
    USE SIGNAL ;
    PORT
      LAYER met3 ;
        RECT 652.960000 137.470000 653.760000 137.770000 ;
    END
  END mdu_remainder[6]
  PIN mdu_remainder[5]
    DIRECTION INPUT ;
    USE SIGNAL ;
    PORT
      LAYER met2 ;
        RECT 460.970000 0.000000 461.110000 0.485000 ;
    END
  END mdu_remainder[5]
  PIN mdu_remainder[4]
    DIRECTION INPUT ;
    USE SIGNAL ;
    PORT
      LAYER met2 ;
        RECT 464.810000 0.000000 464.950000 0.485000 ;
    END
  END mdu_remainder[4]
  PIN mdu_remainder[3]
    DIRECTION INPUT ;
    USE SIGNAL ;
    PORT
      LAYER met3 ;
        RECT 652.960000 277.770000 653.760000 278.070000 ;
    END
  END mdu_remainder[3]
  PIN mdu_remainder[2]
    DIRECTION INPUT ;
    USE SIGNAL ;
    PORT
      LAYER met3 ;
        RECT 652.960000 136.250000 653.760000 136.550000 ;
    END
  END mdu_remainder[2]
  PIN mdu_remainder[1]
    DIRECTION INPUT ;
    USE SIGNAL ;
    PORT
      LAYER met3 ;
        RECT 652.960000 278.990000 653.760000 279.290000 ;
    END
  END mdu_remainder[1]
  PIN mdu_remainder[0]
    DIRECTION INPUT ;
    USE SIGNAL ;
    PORT
      LAYER met3 ;
        RECT 652.960000 280.210000 653.760000 280.510000 ;
    END
  END mdu_remainder[0]
  PIN interrupts[31]
    DIRECTION INPUT ;
    USE SIGNAL ;
    PORT
      LAYER met3 ;
        RECT 652.960000 469.920000 653.760000 470.220000 ;
    END
  END interrupts[31]
  PIN interrupts[30]
    DIRECTION INPUT ;
    USE SIGNAL ;
    PORT
      LAYER met3 ;
        RECT 652.960000 476.630000 653.760000 476.930000 ;
    END
  END interrupts[30]
  PIN interrupts[29]
    DIRECTION INPUT ;
    USE SIGNAL ;
    PORT
      LAYER met3 ;
        RECT 652.960000 489.440000 653.760000 489.740000 ;
    END
  END interrupts[29]
  PIN interrupts[28]
    DIRECTION INPUT ;
    USE SIGNAL ;
    PORT
      LAYER met3 ;
        RECT 652.960000 490.660000 653.760000 490.960000 ;
    END
  END interrupts[28]
  PIN interrupts[27]
    DIRECTION INPUT ;
    USE SIGNAL ;
    PORT
      LAYER met2 ;
        RECT 509.930000 646.275000 510.070000 646.760000 ;
    END
  END interrupts[27]
  PIN interrupts[26]
    DIRECTION INPUT ;
    USE SIGNAL ;
    PORT
      LAYER met2 ;
        RECT 505.130000 646.275000 505.270000 646.760000 ;
    END
  END interrupts[26]
  PIN interrupts[25]
    DIRECTION INPUT ;
    USE SIGNAL ;
    PORT
      LAYER met2 ;
        RECT 511.370000 646.275000 511.510000 646.760000 ;
    END
  END interrupts[25]
  PIN interrupts[24]
    DIRECTION INPUT ;
    USE SIGNAL ;
    PORT
      LAYER met2 ;
        RECT 508.010000 646.275000 508.150000 646.760000 ;
    END
  END interrupts[24]
  PIN interrupts[23]
    DIRECTION INPUT ;
    USE SIGNAL ;
    PORT
      LAYER met2 ;
        RECT 477.290000 646.275000 477.430000 646.760000 ;
    END
  END interrupts[23]
  PIN interrupts[22]
    DIRECTION INPUT ;
    USE SIGNAL ;
    PORT
      LAYER met2 ;
        RECT 472.970000 646.275000 473.110000 646.760000 ;
    END
  END interrupts[22]
  PIN interrupts[21]
    DIRECTION INPUT ;
    USE SIGNAL ;
    PORT
      LAYER met2 ;
        RECT 487.370000 646.275000 487.510000 646.760000 ;
    END
  END interrupts[21]
  PIN interrupts[20]
    DIRECTION INPUT ;
    USE SIGNAL ;
    PORT
      LAYER met2 ;
        RECT 474.890000 646.275000 475.030000 646.760000 ;
    END
  END interrupts[20]
  PIN interrupts[19]
    DIRECTION INPUT ;
    USE SIGNAL ;
    PORT
      LAYER met2 ;
        RECT 484.010000 646.275000 484.150000 646.760000 ;
    END
  END interrupts[19]
  PIN interrupts[18]
    DIRECTION INPUT ;
    USE SIGNAL ;
    PORT
      LAYER met2 ;
        RECT 484.970000 646.275000 485.110000 646.760000 ;
    END
  END interrupts[18]
  PIN interrupts[17]
    DIRECTION INPUT ;
    USE SIGNAL ;
    PORT
      LAYER met2 ;
        RECT 482.570000 646.275000 482.710000 646.760000 ;
    END
  END interrupts[17]
  PIN interrupts[16]
    DIRECTION INPUT ;
    USE SIGNAL ;
    PORT
      LAYER met2 ;
        RECT 486.410000 646.275000 486.550000 646.760000 ;
    END
  END interrupts[16]
  PIN interrupts[15]
    DIRECTION INPUT ;
    USE SIGNAL ;
    PORT
      LAYER met3 ;
        RECT 652.960000 449.790000 653.760000 450.090000 ;
    END
  END interrupts[15]
  PIN interrupts[14]
    DIRECTION INPUT ;
    USE SIGNAL ;
    PORT
      LAYER met3 ;
        RECT 652.960000 443.080000 653.760000 443.380000 ;
    END
  END interrupts[14]
  PIN interrupts[13]
    DIRECTION INPUT ;
    USE SIGNAL ;
    PORT
      LAYER met3 ;
        RECT 652.960000 436.370000 653.760000 436.670000 ;
    END
  END interrupts[13]
  PIN interrupts[12]
    DIRECTION INPUT ;
    USE SIGNAL ;
    PORT
      LAYER met5 ;
        RECT 651.260000 435.110000 653.760000 436.710000 ;
    END
  END interrupts[12]
  PIN interrupts[11]
    DIRECTION INPUT ;
    USE SIGNAL ;
    PORT
      LAYER met3 ;
        RECT 652.960000 416.240000 653.760000 416.540000 ;
    END
  END interrupts[11]
  PIN interrupts[10]
    DIRECTION INPUT ;
    USE SIGNAL ;
    PORT
      LAYER met3 ;
        RECT 652.960000 422.950000 653.760000 423.250000 ;
    END
  END interrupts[10]
  PIN interrupts[9]
    DIRECTION INPUT ;
    USE SIGNAL ;
    PORT
      LAYER met3 ;
        RECT 652.960000 409.530000 653.760000 409.830000 ;
    END
  END interrupts[9]
  PIN interrupts[8]
    DIRECTION INPUT ;
    USE SIGNAL ;
    PORT
      LAYER met5 ;
        RECT 651.260000 409.490000 653.760000 411.090000 ;
    END
  END interrupts[8]
  PIN interrupts[7]
    DIRECTION INPUT ;
    USE SIGNAL ;
    PORT
      LAYER met3 ;
        RECT 652.960000 376.590000 653.760000 376.890000 ;
    END
  END interrupts[7]
  PIN interrupts[6]
    DIRECTION INPUT ;
    USE SIGNAL ;
    PORT
      LAYER met5 ;
        RECT 651.260000 376.550000 653.760000 378.150000 ;
    END
  END interrupts[6]
  PIN interrupts[5]
    DIRECTION INPUT ;
    USE SIGNAL ;
    PORT
      LAYER met3 ;
        RECT 652.960000 375.370000 653.760000 375.670000 ;
    END
  END interrupts[5]
  PIN interrupts[4]
    DIRECTION INPUT ;
    USE SIGNAL ;
    PORT
      LAYER met3 ;
        RECT 652.960000 377.810000 653.760000 378.110000 ;
    END
  END interrupts[4]
  PIN interrupts[3]
    DIRECTION INPUT ;
    USE SIGNAL ;
    PORT
      LAYER met5 ;
        RECT 651.260000 361.910000 653.760000 363.510000 ;
    END
  END interrupts[3]
  PIN interrupts[2]
    DIRECTION INPUT ;
    USE SIGNAL ;
    PORT
      LAYER met3 ;
        RECT 652.960000 369.880000 653.760000 370.180000 ;
    END
  END interrupts[2]
  PIN interrupts[1]
    DIRECTION INPUT ;
    USE SIGNAL ;
    PORT
      LAYER met5 ;
        RECT 651.260000 369.230000 653.760000 370.830000 ;
    END
  END interrupts[1]
  PIN interrupts[0]
    DIRECTION INPUT ;
    USE SIGNAL ;
    PORT
      LAYER met3 ;
        RECT 652.960000 379.030000 653.760000 379.330000 ;
    END
  END interrupts[0]
  OBS
    LAYER met1 ;
      RECT 0.000000 0.000000 653.760000 646.760000 ;
    LAYER met2 ;
      RECT 511.650000 646.135000 653.760000 646.760000 ;
      RECT 510.210000 646.135000 511.230000 646.760000 ;
      RECT 508.290000 646.135000 509.790000 646.760000 ;
      RECT 505.410000 646.135000 507.870000 646.760000 ;
      RECT 487.650000 646.135000 504.990000 646.760000 ;
      RECT 486.690000 646.135000 487.230000 646.760000 ;
      RECT 485.250000 646.135000 486.270000 646.760000 ;
      RECT 484.290000 646.135000 484.830000 646.760000 ;
      RECT 482.850000 646.135000 483.870000 646.760000 ;
      RECT 477.570000 646.135000 482.430000 646.760000 ;
      RECT 475.170000 646.135000 477.150000 646.760000 ;
      RECT 473.250000 646.135000 474.750000 646.760000 ;
      RECT 428.130000 646.135000 472.830000 646.760000 ;
      RECT 425.250000 646.135000 427.710000 646.760000 ;
      RECT 423.810000 646.135000 424.830000 646.760000 ;
      RECT 419.970000 646.135000 423.390000 646.760000 ;
      RECT 416.130000 646.135000 419.550000 646.760000 ;
      RECT 414.690000 646.135000 415.710000 646.760000 ;
      RECT 413.250000 646.135000 414.270000 646.760000 ;
      RECT 411.330000 646.135000 412.830000 646.760000 ;
      RECT 401.730000 646.135000 410.910000 646.760000 ;
      RECT 399.330000 646.135000 401.310000 646.760000 ;
      RECT 397.410000 646.135000 398.910000 646.760000 ;
      RECT 396.450000 646.135000 396.990000 646.760000 ;
      RECT 395.490000 646.135000 396.030000 646.760000 ;
      RECT 394.530000 646.135000 395.070000 646.760000 ;
      RECT 393.570000 646.135000 394.110000 646.760000 ;
      RECT 392.610000 646.135000 393.150000 646.760000 ;
      RECT 391.650000 646.135000 392.190000 646.760000 ;
      RECT 390.210000 646.135000 391.230000 646.760000 ;
      RECT 389.250000 646.135000 389.790000 646.760000 ;
      RECT 388.290000 646.135000 388.830000 646.760000 ;
      RECT 387.330000 646.135000 387.870000 646.760000 ;
      RECT 386.370000 646.135000 386.910000 646.760000 ;
      RECT 385.410000 646.135000 385.950000 646.760000 ;
      RECT 382.050000 646.135000 384.990000 646.760000 ;
      RECT 381.090000 646.135000 381.630000 646.760000 ;
      RECT 380.130000 646.135000 380.670000 646.760000 ;
      RECT 379.170000 646.135000 379.710000 646.760000 ;
      RECT 377.250000 646.135000 378.750000 646.760000 ;
      RECT 376.290000 646.135000 376.830000 646.760000 ;
      RECT 373.890000 646.135000 375.870000 646.760000 ;
      RECT 371.490000 646.135000 373.470000 646.760000 ;
      RECT 367.650000 646.135000 371.070000 646.760000 ;
      RECT 364.770000 646.135000 367.230000 646.760000 ;
      RECT 361.410000 646.135000 364.350000 646.760000 ;
      RECT 358.530000 646.135000 360.990000 646.760000 ;
      RECT 354.690000 646.135000 358.110000 646.760000 ;
      RECT 351.810000 646.135000 354.270000 646.760000 ;
      RECT 348.930000 646.135000 351.390000 646.760000 ;
      RECT 327.810000 646.135000 348.510000 646.760000 ;
      RECT 326.850000 646.135000 327.390000 646.760000 ;
      RECT 323.010000 646.135000 326.430000 646.760000 ;
      RECT 322.050000 646.135000 322.590000 646.760000 ;
      RECT 320.610000 646.135000 321.630000 646.760000 ;
      RECT 319.650000 646.135000 320.190000 646.760000 ;
      RECT 318.690000 646.135000 319.230000 646.760000 ;
      RECT 317.730000 646.135000 318.270000 646.760000 ;
      RECT 316.770000 646.135000 317.310000 646.760000 ;
      RECT 315.810000 646.135000 316.350000 646.760000 ;
      RECT 314.850000 646.135000 315.390000 646.760000 ;
      RECT 313.410000 646.135000 314.430000 646.760000 ;
      RECT 311.970000 646.135000 312.990000 646.760000 ;
      RECT 311.010000 646.135000 311.550000 646.760000 ;
      RECT 309.570000 646.135000 310.590000 646.760000 ;
      RECT 308.610000 646.135000 309.150000 646.760000 ;
      RECT 307.650000 646.135000 308.190000 646.760000 ;
      RECT 306.690000 646.135000 307.230000 646.760000 ;
      RECT 304.290000 646.135000 306.270000 646.760000 ;
      RECT 302.850000 646.135000 303.870000 646.760000 ;
      RECT 300.450000 646.135000 302.430000 646.760000 ;
      RECT 297.570000 646.135000 300.030000 646.760000 ;
      RECT 296.610000 646.135000 297.150000 646.760000 ;
      RECT 295.650000 646.135000 296.190000 646.760000 ;
      RECT 293.250000 646.135000 295.230000 646.760000 ;
      RECT 289.890000 646.135000 292.830000 646.760000 ;
      RECT 287.490000 646.135000 289.470000 646.760000 ;
      RECT 286.530000 646.135000 287.070000 646.760000 ;
      RECT 285.570000 646.135000 286.110000 646.760000 ;
      RECT 284.130000 646.135000 285.150000 646.760000 ;
      RECT 283.170000 646.135000 283.710000 646.760000 ;
      RECT 282.210000 646.135000 282.750000 646.760000 ;
      RECT 281.250000 646.135000 281.790000 646.760000 ;
      RECT 280.290000 646.135000 280.830000 646.760000 ;
      RECT 279.330000 646.135000 279.870000 646.760000 ;
      RECT 278.370000 646.135000 278.910000 646.760000 ;
      RECT 275.970000 646.135000 277.950000 646.760000 ;
      RECT 275.010000 646.135000 275.550000 646.760000 ;
      RECT 272.610000 646.135000 274.590000 646.760000 ;
      RECT 271.650000 646.135000 272.190000 646.760000 ;
      RECT 259.650000 646.135000 271.230000 646.760000 ;
      RECT 258.690000 646.135000 259.230000 646.760000 ;
      RECT 251.490000 646.135000 258.270000 646.760000 ;
      RECT 250.530000 646.135000 251.070000 646.760000 ;
      RECT 249.090000 646.135000 250.110000 646.760000 ;
      RECT 248.130000 646.135000 248.670000 646.760000 ;
      RECT 244.290000 646.135000 247.710000 646.760000 ;
      RECT 243.330000 646.135000 243.870000 646.760000 ;
      RECT 0.000000 646.135000 242.910000 646.760000 ;
      RECT 0.000000 0.625000 653.760000 646.135000 ;
      RECT 481.410000 0.000000 653.760000 0.625000 ;
      RECT 480.450000 0.000000 480.990000 0.625000 ;
      RECT 478.530000 0.000000 480.030000 0.625000 ;
      RECT 477.570000 0.000000 478.110000 0.625000 ;
      RECT 476.130000 0.000000 477.150000 0.625000 ;
      RECT 474.690000 0.000000 475.710000 0.625000 ;
      RECT 473.730000 0.000000 474.270000 0.625000 ;
      RECT 472.770000 0.000000 473.310000 0.625000 ;
      RECT 470.850000 0.000000 472.350000 0.625000 ;
      RECT 469.410000 0.000000 470.430000 0.625000 ;
      RECT 468.450000 0.000000 468.990000 0.625000 ;
      RECT 467.010000 0.000000 468.030000 0.625000 ;
      RECT 466.050000 0.000000 466.590000 0.625000 ;
      RECT 465.090000 0.000000 465.630000 0.625000 ;
      RECT 463.650000 0.000000 464.670000 0.625000 ;
      RECT 462.690000 0.000000 463.230000 0.625000 ;
      RECT 461.250000 0.000000 462.270000 0.625000 ;
      RECT 459.810000 0.000000 460.830000 0.625000 ;
      RECT 458.850000 0.000000 459.390000 0.625000 ;
      RECT 457.890000 0.000000 458.430000 0.625000 ;
      RECT 456.930000 0.000000 457.470000 0.625000 ;
      RECT 455.970000 0.000000 456.510000 0.625000 ;
      RECT 455.010000 0.000000 455.550000 0.625000 ;
      RECT 453.570000 0.000000 454.590000 0.625000 ;
      RECT 451.650000 0.000000 453.150000 0.625000 ;
      RECT 450.210000 0.000000 451.230000 0.625000 ;
      RECT 449.250000 0.000000 449.790000 0.625000 ;
      RECT 448.290000 0.000000 448.830000 0.625000 ;
      RECT 446.850000 0.000000 447.870000 0.625000 ;
      RECT 443.490000 0.000000 446.430000 0.625000 ;
      RECT 419.490000 0.000000 443.070000 0.625000 ;
      RECT 418.530000 0.000000 419.070000 0.625000 ;
      RECT 412.770000 0.000000 418.110000 0.625000 ;
      RECT 391.650000 0.000000 412.350000 0.625000 ;
      RECT 378.690000 0.000000 391.230000 0.625000 ;
      RECT 377.730000 0.000000 378.270000 0.625000 ;
      RECT 371.970000 0.000000 377.310000 0.625000 ;
      RECT 364.770000 0.000000 371.550000 0.625000 ;
      RECT 362.850000 0.000000 364.350000 0.625000 ;
      RECT 358.530000 0.000000 362.430000 0.625000 ;
      RECT 357.570000 0.000000 358.110000 0.625000 ;
      RECT 356.130000 0.000000 357.150000 0.625000 ;
      RECT 352.290000 0.000000 355.710000 0.625000 ;
      RECT 336.450000 0.000000 351.870000 0.625000 ;
      RECT 335.490000 0.000000 336.030000 0.625000 ;
      RECT 330.210000 0.000000 335.070000 0.625000 ;
      RECT 326.850000 0.000000 329.790000 0.625000 ;
      RECT 314.850000 0.000000 326.430000 0.625000 ;
      RECT 313.890000 0.000000 314.430000 0.625000 ;
      RECT 312.930000 0.000000 313.470000 0.625000 ;
      RECT 311.970000 0.000000 312.510000 0.625000 ;
      RECT 0.000000 0.000000 311.550000 0.625000 ;
    LAYER met3 ;
      RECT 0.000000 491.260000 653.760000 646.760000 ;
      RECT 0.000000 490.360000 652.660000 491.260000 ;
      RECT 0.000000 490.040000 653.760000 490.360000 ;
      RECT 0.000000 489.140000 652.660000 490.040000 ;
      RECT 0.000000 477.230000 653.760000 489.140000 ;
      RECT 0.000000 476.330000 652.660000 477.230000 ;
      RECT 0.000000 470.520000 653.760000 476.330000 ;
      RECT 0.000000 469.620000 652.660000 470.520000 ;
      RECT 0.000000 450.390000 653.760000 469.620000 ;
      RECT 0.000000 449.490000 652.660000 450.390000 ;
      RECT 0.000000 443.680000 653.760000 449.490000 ;
      RECT 0.000000 442.780000 652.660000 443.680000 ;
      RECT 0.000000 436.970000 653.760000 442.780000 ;
      RECT 0.000000 436.070000 652.660000 436.970000 ;
      RECT 0.000000 423.550000 653.760000 436.070000 ;
      RECT 0.000000 422.650000 652.660000 423.550000 ;
      RECT 0.000000 416.840000 653.760000 422.650000 ;
      RECT 0.000000 415.940000 652.660000 416.840000 ;
      RECT 0.000000 412.570000 653.760000 415.940000 ;
      RECT 0.000000 411.670000 652.660000 412.570000 ;
      RECT 0.000000 411.350000 653.760000 411.670000 ;
      RECT 0.000000 410.450000 652.660000 411.350000 ;
      RECT 0.000000 410.130000 653.760000 410.450000 ;
      RECT 0.000000 409.230000 652.660000 410.130000 ;
      RECT 0.000000 393.660000 653.760000 409.230000 ;
      RECT 0.000000 392.760000 652.660000 393.660000 ;
      RECT 0.000000 384.510000 653.760000 392.760000 ;
      RECT 0.000000 383.610000 652.660000 384.510000 ;
      RECT 0.000000 383.290000 653.760000 383.610000 ;
      RECT 0.000000 382.390000 652.660000 383.290000 ;
      RECT 0.000000 382.070000 653.760000 382.390000 ;
      RECT 0.000000 381.170000 652.660000 382.070000 ;
      RECT 0.000000 380.850000 653.760000 381.170000 ;
      RECT 0.000000 379.950000 652.660000 380.850000 ;
      RECT 0.000000 379.630000 653.760000 379.950000 ;
      RECT 0.000000 378.730000 652.660000 379.630000 ;
      RECT 0.000000 378.410000 653.760000 378.730000 ;
      RECT 0.000000 377.510000 652.660000 378.410000 ;
      RECT 0.000000 377.190000 653.760000 377.510000 ;
      RECT 0.000000 376.290000 652.660000 377.190000 ;
      RECT 0.000000 375.970000 653.760000 376.290000 ;
      RECT 0.000000 375.070000 652.660000 375.970000 ;
      RECT 0.000000 374.750000 653.760000 375.070000 ;
      RECT 1.100000 374.140000 653.760000 374.750000 ;
      RECT 1.100000 373.850000 652.660000 374.140000 ;
      RECT 0.000000 373.530000 652.660000 373.850000 ;
      RECT 1.100000 373.240000 652.660000 373.530000 ;
      RECT 1.100000 372.630000 653.760000 373.240000 ;
      RECT 0.000000 372.310000 653.760000 372.630000 ;
      RECT 0.000000 371.410000 652.660000 372.310000 ;
      RECT 0.000000 370.480000 653.760000 371.410000 ;
      RECT 0.000000 369.580000 652.660000 370.480000 ;
      RECT 0.000000 368.040000 653.760000 369.580000 ;
      RECT 1.100000 367.140000 652.660000 368.040000 ;
      RECT 0.000000 366.820000 653.760000 367.140000 ;
      RECT 1.100000 365.920000 652.660000 366.820000 ;
      RECT 0.000000 365.600000 653.760000 365.920000 ;
      RECT 0.000000 364.700000 652.660000 365.600000 ;
      RECT 0.000000 363.770000 653.760000 364.700000 ;
      RECT 0.000000 362.870000 652.660000 363.770000 ;
      RECT 0.000000 361.940000 653.760000 362.870000 ;
      RECT 0.000000 361.040000 652.660000 361.940000 ;
      RECT 0.000000 355.840000 653.760000 361.040000 ;
      RECT 1.100000 354.940000 653.760000 355.840000 ;
      RECT 0.000000 354.620000 653.760000 354.940000 ;
      RECT 1.100000 354.010000 653.760000 354.620000 ;
      RECT 1.100000 353.720000 652.660000 354.010000 ;
      RECT 0.000000 353.400000 652.660000 353.720000 ;
      RECT 1.100000 353.110000 652.660000 353.400000 ;
      RECT 1.100000 352.500000 653.760000 353.110000 ;
      RECT 0.000000 352.180000 653.760000 352.500000 ;
      RECT 1.100000 351.280000 653.760000 352.180000 ;
      RECT 0.000000 349.130000 653.760000 351.280000 ;
      RECT 1.100000 348.520000 653.760000 349.130000 ;
      RECT 1.100000 348.230000 652.660000 348.520000 ;
      RECT 0.000000 347.910000 652.660000 348.230000 ;
      RECT 1.100000 347.620000 652.660000 347.910000 ;
      RECT 1.100000 347.010000 653.760000 347.620000 ;
      RECT 0.000000 346.690000 653.760000 347.010000 ;
      RECT 1.100000 345.790000 653.760000 346.690000 ;
      RECT 0.000000 344.860000 653.760000 345.790000 ;
      RECT 1.100000 343.960000 652.660000 344.860000 ;
      RECT 0.000000 343.640000 653.760000 343.960000 ;
      RECT 1.100000 342.740000 652.660000 343.640000 ;
      RECT 0.000000 341.200000 653.760000 342.740000 ;
      RECT 0.000000 340.300000 652.660000 341.200000 ;
      RECT 0.000000 338.150000 653.760000 340.300000 ;
      RECT 1.100000 337.540000 653.760000 338.150000 ;
      RECT 1.100000 337.250000 652.660000 337.540000 ;
      RECT 0.000000 336.930000 652.660000 337.250000 ;
      RECT 1.100000 336.640000 652.660000 336.930000 ;
      RECT 1.100000 336.320000 653.760000 336.640000 ;
      RECT 1.100000 336.030000 652.660000 336.320000 ;
      RECT 0.000000 335.710000 652.660000 336.030000 ;
      RECT 1.100000 335.420000 652.660000 335.710000 ;
      RECT 1.100000 334.810000 653.760000 335.420000 ;
      RECT 0.000000 334.490000 653.760000 334.810000 ;
      RECT 1.100000 333.590000 653.760000 334.490000 ;
      RECT 0.000000 329.610000 653.760000 333.590000 ;
      RECT 0.000000 328.710000 652.660000 329.610000 ;
      RECT 0.000000 325.950000 653.760000 328.710000 ;
      RECT 1.100000 325.050000 653.760000 325.950000 ;
      RECT 0.000000 324.730000 653.760000 325.050000 ;
      RECT 1.100000 324.120000 653.760000 324.730000 ;
      RECT 1.100000 323.830000 652.660000 324.120000 ;
      RECT 0.000000 323.510000 652.660000 323.830000 ;
      RECT 1.100000 323.220000 652.660000 323.510000 ;
      RECT 1.100000 322.610000 653.760000 323.220000 ;
      RECT 0.000000 322.290000 653.760000 322.610000 ;
      RECT 1.100000 321.390000 653.760000 322.290000 ;
      RECT 0.000000 318.630000 653.760000 321.390000 ;
      RECT 0.000000 317.730000 652.660000 318.630000 ;
      RECT 0.000000 317.410000 653.760000 317.730000 ;
      RECT 0.000000 316.510000 652.660000 317.410000 ;
      RECT 0.000000 316.190000 653.760000 316.510000 ;
      RECT 0.000000 315.290000 652.660000 316.190000 ;
      RECT 0.000000 310.700000 653.760000 315.290000 ;
      RECT 0.000000 309.800000 652.660000 310.700000 ;
      RECT 0.000000 308.260000 653.760000 309.800000 ;
      RECT 1.100000 307.360000 653.760000 308.260000 ;
      RECT 0.000000 307.040000 653.760000 307.360000 ;
      RECT 1.100000 306.140000 653.760000 307.040000 ;
      RECT 0.000000 295.450000 653.760000 306.140000 ;
      RECT 0.000000 294.550000 652.660000 295.450000 ;
      RECT 0.000000 288.130000 653.760000 294.550000 ;
      RECT 0.000000 287.230000 652.660000 288.130000 ;
      RECT 0.000000 285.690000 653.760000 287.230000 ;
      RECT 0.000000 284.790000 652.660000 285.690000 ;
      RECT 0.000000 284.470000 653.760000 284.790000 ;
      RECT 0.000000 283.570000 652.660000 284.470000 ;
      RECT 0.000000 283.250000 653.760000 283.570000 ;
      RECT 0.000000 282.350000 652.660000 283.250000 ;
      RECT 0.000000 282.030000 653.760000 282.350000 ;
      RECT 0.000000 281.130000 652.660000 282.030000 ;
      RECT 0.000000 280.810000 653.760000 281.130000 ;
      RECT 0.000000 279.910000 652.660000 280.810000 ;
      RECT 0.000000 279.590000 653.760000 279.910000 ;
      RECT 0.000000 278.690000 652.660000 279.590000 ;
      RECT 0.000000 278.370000 653.760000 278.690000 ;
      RECT 0.000000 277.470000 652.660000 278.370000 ;
      RECT 0.000000 277.150000 653.760000 277.470000 ;
      RECT 0.000000 276.250000 652.660000 277.150000 ;
      RECT 0.000000 275.930000 653.760000 276.250000 ;
      RECT 0.000000 275.030000 652.660000 275.930000 ;
      RECT 0.000000 274.710000 653.760000 275.030000 ;
      RECT 0.000000 273.810000 652.660000 274.710000 ;
      RECT 0.000000 273.490000 653.760000 273.810000 ;
      RECT 0.000000 272.590000 652.660000 273.490000 ;
      RECT 0.000000 272.270000 653.760000 272.590000 ;
      RECT 0.000000 271.370000 652.660000 272.270000 ;
      RECT 0.000000 270.440000 653.760000 271.370000 ;
      RECT 0.000000 269.540000 652.660000 270.440000 ;
      RECT 0.000000 268.610000 653.760000 269.540000 ;
      RECT 0.000000 267.710000 652.660000 268.610000 ;
      RECT 0.000000 267.390000 653.760000 267.710000 ;
      RECT 0.000000 266.490000 652.660000 267.390000 ;
      RECT 0.000000 266.170000 653.760000 266.490000 ;
      RECT 0.000000 265.270000 652.660000 266.170000 ;
      RECT 0.000000 264.950000 653.760000 265.270000 ;
      RECT 0.000000 264.050000 652.660000 264.950000 ;
      RECT 0.000000 263.730000 653.760000 264.050000 ;
      RECT 0.000000 262.830000 652.660000 263.730000 ;
      RECT 0.000000 261.900000 653.760000 262.830000 ;
      RECT 0.000000 261.000000 652.660000 261.900000 ;
      RECT 0.000000 260.680000 653.760000 261.000000 ;
      RECT 0.000000 259.780000 652.660000 260.680000 ;
      RECT 0.000000 259.460000 653.760000 259.780000 ;
      RECT 0.000000 258.560000 652.660000 259.460000 ;
      RECT 0.000000 258.240000 653.760000 258.560000 ;
      RECT 0.000000 257.340000 652.660000 258.240000 ;
      RECT 0.000000 257.020000 653.760000 257.340000 ;
      RECT 0.000000 256.120000 652.660000 257.020000 ;
      RECT 0.000000 255.800000 653.760000 256.120000 ;
      RECT 0.000000 254.900000 652.660000 255.800000 ;
      RECT 0.000000 254.580000 653.760000 254.900000 ;
      RECT 0.000000 253.680000 652.660000 254.580000 ;
      RECT 0.000000 252.750000 653.760000 253.680000 ;
      RECT 0.000000 251.850000 652.660000 252.750000 ;
      RECT 0.000000 251.530000 653.760000 251.850000 ;
      RECT 0.000000 250.630000 652.660000 251.530000 ;
      RECT 0.000000 250.310000 653.760000 250.630000 ;
      RECT 0.000000 249.410000 652.660000 250.310000 ;
      RECT 0.000000 249.090000 653.760000 249.410000 ;
      RECT 0.000000 248.190000 652.660000 249.090000 ;
      RECT 0.000000 247.870000 653.760000 248.190000 ;
      RECT 0.000000 246.970000 652.660000 247.870000 ;
      RECT 0.000000 246.650000 653.760000 246.970000 ;
      RECT 0.000000 245.750000 652.660000 246.650000 ;
      RECT 0.000000 245.430000 653.760000 245.750000 ;
      RECT 0.000000 244.530000 652.660000 245.430000 ;
      RECT 0.000000 244.210000 653.760000 244.530000 ;
      RECT 0.000000 243.310000 652.660000 244.210000 ;
      RECT 0.000000 242.990000 653.760000 243.310000 ;
      RECT 0.000000 242.090000 652.660000 242.990000 ;
      RECT 0.000000 241.770000 653.760000 242.090000 ;
      RECT 0.000000 240.870000 652.660000 241.770000 ;
      RECT 0.000000 239.940000 653.760000 240.870000 ;
      RECT 0.000000 239.040000 652.660000 239.940000 ;
      RECT 0.000000 238.720000 653.760000 239.040000 ;
      RECT 0.000000 237.820000 652.660000 238.720000 ;
      RECT 0.000000 237.500000 653.760000 237.820000 ;
      RECT 0.000000 236.600000 652.660000 237.500000 ;
      RECT 0.000000 236.280000 653.760000 236.600000 ;
      RECT 0.000000 235.380000 652.660000 236.280000 ;
      RECT 0.000000 235.060000 653.760000 235.380000 ;
      RECT 0.000000 234.160000 652.660000 235.060000 ;
      RECT 0.000000 233.840000 653.760000 234.160000 ;
      RECT 0.000000 232.940000 652.660000 233.840000 ;
      RECT 0.000000 232.620000 653.760000 232.940000 ;
      RECT 0.000000 231.720000 652.660000 232.620000 ;
      RECT 0.000000 230.790000 653.760000 231.720000 ;
      RECT 0.000000 229.890000 652.660000 230.790000 ;
      RECT 0.000000 228.960000 653.760000 229.890000 ;
      RECT 0.000000 228.060000 652.660000 228.960000 ;
      RECT 0.000000 227.740000 653.760000 228.060000 ;
      RECT 0.000000 226.840000 652.660000 227.740000 ;
      RECT 0.000000 226.520000 653.760000 226.840000 ;
      RECT 0.000000 225.620000 652.660000 226.520000 ;
      RECT 0.000000 225.300000 653.760000 225.620000 ;
      RECT 0.000000 224.400000 652.660000 225.300000 ;
      RECT 0.000000 224.080000 653.760000 224.400000 ;
      RECT 0.000000 223.180000 652.660000 224.080000 ;
      RECT 0.000000 222.860000 653.760000 223.180000 ;
      RECT 0.000000 221.960000 652.660000 222.860000 ;
      RECT 0.000000 221.640000 653.760000 221.960000 ;
      RECT 0.000000 220.740000 652.660000 221.640000 ;
      RECT 0.000000 219.810000 653.760000 220.740000 ;
      RECT 0.000000 218.910000 652.660000 219.810000 ;
      RECT 0.000000 218.590000 653.760000 218.910000 ;
      RECT 0.000000 217.690000 652.660000 218.590000 ;
      RECT 0.000000 217.370000 653.760000 217.690000 ;
      RECT 0.000000 216.470000 652.660000 217.370000 ;
      RECT 0.000000 216.150000 653.760000 216.470000 ;
      RECT 0.000000 215.250000 652.660000 216.150000 ;
      RECT 0.000000 214.320000 653.760000 215.250000 ;
      RECT 0.000000 213.420000 652.660000 214.320000 ;
      RECT 0.000000 213.100000 653.760000 213.420000 ;
      RECT 0.000000 212.200000 652.660000 213.100000 ;
      RECT 0.000000 211.880000 653.760000 212.200000 ;
      RECT 0.000000 210.980000 652.660000 211.880000 ;
      RECT 0.000000 210.660000 653.760000 210.980000 ;
      RECT 0.000000 209.760000 652.660000 210.660000 ;
      RECT 0.000000 209.440000 653.760000 209.760000 ;
      RECT 0.000000 208.540000 652.660000 209.440000 ;
      RECT 0.000000 207.610000 653.760000 208.540000 ;
      RECT 0.000000 206.710000 652.660000 207.610000 ;
      RECT 0.000000 206.390000 653.760000 206.710000 ;
      RECT 0.000000 205.490000 652.660000 206.390000 ;
      RECT 0.000000 205.170000 653.760000 205.490000 ;
      RECT 0.000000 204.270000 652.660000 205.170000 ;
      RECT 0.000000 203.950000 653.760000 204.270000 ;
      RECT 0.000000 203.050000 652.660000 203.950000 ;
      RECT 0.000000 202.730000 653.760000 203.050000 ;
      RECT 0.000000 201.830000 652.660000 202.730000 ;
      RECT 0.000000 200.900000 653.760000 201.830000 ;
      RECT 0.000000 200.000000 652.660000 200.900000 ;
      RECT 0.000000 199.680000 653.760000 200.000000 ;
      RECT 0.000000 198.780000 652.660000 199.680000 ;
      RECT 0.000000 198.460000 653.760000 198.780000 ;
      RECT 0.000000 197.560000 652.660000 198.460000 ;
      RECT 0.000000 197.240000 653.760000 197.560000 ;
      RECT 0.000000 196.340000 652.660000 197.240000 ;
      RECT 0.000000 195.410000 653.760000 196.340000 ;
      RECT 0.000000 194.510000 652.660000 195.410000 ;
      RECT 0.000000 194.190000 653.760000 194.510000 ;
      RECT 0.000000 193.290000 652.660000 194.190000 ;
      RECT 0.000000 192.970000 653.760000 193.290000 ;
      RECT 0.000000 192.070000 652.660000 192.970000 ;
      RECT 0.000000 191.750000 653.760000 192.070000 ;
      RECT 0.000000 190.850000 652.660000 191.750000 ;
      RECT 0.000000 190.530000 653.760000 190.850000 ;
      RECT 0.000000 189.630000 652.660000 190.530000 ;
      RECT 0.000000 189.310000 653.760000 189.630000 ;
      RECT 0.000000 188.410000 652.660000 189.310000 ;
      RECT 0.000000 188.090000 653.760000 188.410000 ;
      RECT 0.000000 187.190000 652.660000 188.090000 ;
      RECT 0.000000 186.870000 653.760000 187.190000 ;
      RECT 0.000000 185.970000 652.660000 186.870000 ;
      RECT 0.000000 185.650000 653.760000 185.970000 ;
      RECT 0.000000 184.750000 652.660000 185.650000 ;
      RECT 0.000000 184.430000 653.760000 184.750000 ;
      RECT 0.000000 183.530000 652.660000 184.430000 ;
      RECT 0.000000 183.210000 653.760000 183.530000 ;
      RECT 0.000000 182.310000 652.660000 183.210000 ;
      RECT 0.000000 181.990000 653.760000 182.310000 ;
      RECT 0.000000 181.090000 652.660000 181.990000 ;
      RECT 0.000000 180.770000 653.760000 181.090000 ;
      RECT 0.000000 179.870000 652.660000 180.770000 ;
      RECT 0.000000 179.550000 653.760000 179.870000 ;
      RECT 0.000000 178.650000 652.660000 179.550000 ;
      RECT 0.000000 178.330000 653.760000 178.650000 ;
      RECT 0.000000 177.430000 652.660000 178.330000 ;
      RECT 0.000000 177.110000 653.760000 177.430000 ;
      RECT 0.000000 176.210000 652.660000 177.110000 ;
      RECT 0.000000 175.890000 653.760000 176.210000 ;
      RECT 0.000000 174.990000 652.660000 175.890000 ;
      RECT 0.000000 174.670000 653.760000 174.990000 ;
      RECT 0.000000 173.770000 652.660000 174.670000 ;
      RECT 0.000000 172.840000 653.760000 173.770000 ;
      RECT 0.000000 171.940000 652.660000 172.840000 ;
      RECT 0.000000 171.620000 653.760000 171.940000 ;
      RECT 0.000000 170.720000 652.660000 171.620000 ;
      RECT 0.000000 170.400000 653.760000 170.720000 ;
      RECT 0.000000 169.500000 652.660000 170.400000 ;
      RECT 0.000000 169.180000 653.760000 169.500000 ;
      RECT 0.000000 168.280000 652.660000 169.180000 ;
      RECT 0.000000 167.960000 653.760000 168.280000 ;
      RECT 0.000000 167.060000 652.660000 167.960000 ;
      RECT 0.000000 166.130000 653.760000 167.060000 ;
      RECT 0.000000 165.230000 652.660000 166.130000 ;
      RECT 0.000000 164.910000 653.760000 165.230000 ;
      RECT 0.000000 164.010000 652.660000 164.910000 ;
      RECT 0.000000 163.690000 653.760000 164.010000 ;
      RECT 0.000000 162.790000 652.660000 163.690000 ;
      RECT 0.000000 162.470000 653.760000 162.790000 ;
      RECT 0.000000 161.570000 652.660000 162.470000 ;
      RECT 0.000000 161.250000 653.760000 161.570000 ;
      RECT 0.000000 160.350000 652.660000 161.250000 ;
      RECT 0.000000 160.030000 653.760000 160.350000 ;
      RECT 0.000000 159.130000 652.660000 160.030000 ;
      RECT 0.000000 158.810000 653.760000 159.130000 ;
      RECT 0.000000 157.910000 652.660000 158.810000 ;
      RECT 0.000000 157.590000 653.760000 157.910000 ;
      RECT 0.000000 156.690000 652.660000 157.590000 ;
      RECT 0.000000 156.370000 653.760000 156.690000 ;
      RECT 0.000000 155.470000 652.660000 156.370000 ;
      RECT 0.000000 155.150000 653.760000 155.470000 ;
      RECT 0.000000 154.250000 652.660000 155.150000 ;
      RECT 0.000000 153.930000 653.760000 154.250000 ;
      RECT 0.000000 153.030000 652.660000 153.930000 ;
      RECT 0.000000 152.710000 653.760000 153.030000 ;
      RECT 0.000000 151.810000 652.660000 152.710000 ;
      RECT 0.000000 150.880000 653.760000 151.810000 ;
      RECT 0.000000 149.980000 652.660000 150.880000 ;
      RECT 0.000000 149.660000 653.760000 149.980000 ;
      RECT 0.000000 148.760000 652.660000 149.660000 ;
      RECT 0.000000 148.440000 653.760000 148.760000 ;
      RECT 0.000000 147.540000 652.660000 148.440000 ;
      RECT 0.000000 147.220000 653.760000 147.540000 ;
      RECT 0.000000 146.320000 652.660000 147.220000 ;
      RECT 0.000000 146.000000 653.760000 146.320000 ;
      RECT 0.000000 145.100000 652.660000 146.000000 ;
      RECT 0.000000 144.170000 653.760000 145.100000 ;
      RECT 0.000000 143.270000 652.660000 144.170000 ;
      RECT 0.000000 142.950000 653.760000 143.270000 ;
      RECT 0.000000 142.050000 652.660000 142.950000 ;
      RECT 0.000000 141.730000 653.760000 142.050000 ;
      RECT 0.000000 140.830000 652.660000 141.730000 ;
      RECT 0.000000 140.510000 653.760000 140.830000 ;
      RECT 0.000000 139.610000 652.660000 140.510000 ;
      RECT 0.000000 139.290000 653.760000 139.610000 ;
      RECT 0.000000 138.390000 652.660000 139.290000 ;
      RECT 0.000000 138.070000 653.760000 138.390000 ;
      RECT 0.000000 137.170000 652.660000 138.070000 ;
      RECT 0.000000 136.850000 653.760000 137.170000 ;
      RECT 0.000000 135.950000 652.660000 136.850000 ;
      RECT 0.000000 0.000000 653.760000 135.950000 ;
    LAYER met4 ;
      RECT 396.750000 645.660000 653.760000 646.760000 ;
      RECT 395.520000 645.660000 395.850000 646.760000 ;
      RECT 394.290000 645.660000 394.620000 646.760000 ;
      RECT 393.060000 645.660000 393.390000 646.760000 ;
      RECT 391.830000 645.660000 392.160000 646.760000 ;
      RECT 389.985000 645.660000 390.930000 646.760000 ;
      RECT 388.140000 645.660000 389.085000 646.760000 ;
      RECT 386.910000 645.660000 387.240000 646.760000 ;
      RECT 382.605000 645.660000 386.010000 646.760000 ;
      RECT 381.375000 645.660000 381.705000 646.760000 ;
      RECT 380.145000 645.660000 380.475000 646.760000 ;
      RECT 378.915000 645.660000 379.245000 646.760000 ;
      RECT 377.685000 645.660000 378.015000 646.760000 ;
      RECT 376.455000 645.660000 376.785000 646.760000 ;
      RECT 327.255000 645.660000 375.555000 646.760000 ;
      RECT 320.490000 645.660000 326.355000 646.760000 ;
      RECT 319.260000 645.660000 319.590000 646.760000 ;
      RECT 318.030000 645.660000 318.360000 646.760000 ;
      RECT 316.800000 645.660000 317.130000 646.760000 ;
      RECT 314.955000 645.660000 315.900000 646.760000 ;
      RECT 313.725000 645.660000 314.055000 646.760000 ;
      RECT 312.495000 645.660000 312.825000 646.760000 ;
      RECT 308.805000 645.660000 311.595000 646.760000 ;
      RECT 307.575000 645.660000 307.905000 646.760000 ;
      RECT 298.350000 645.660000 306.675000 646.760000 ;
      RECT 297.120000 645.660000 297.450000 646.760000 ;
      RECT 295.890000 645.660000 296.220000 646.760000 ;
      RECT 288.510000 645.660000 294.990000 646.760000 ;
      RECT 287.280000 645.660000 287.610000 646.760000 ;
      RECT 286.050000 645.660000 286.380000 646.760000 ;
      RECT 284.820000 645.660000 285.150000 646.760000 ;
      RECT 281.130000 645.660000 283.920000 646.760000 ;
      RECT 279.285000 645.660000 280.230000 646.760000 ;
      RECT 278.055000 645.660000 278.385000 646.760000 ;
      RECT 276.210000 645.660000 277.155000 646.760000 ;
      RECT 0.000000 645.660000 275.310000 646.760000 ;
      RECT 0.000000 1.100000 653.760000 645.660000 ;
      RECT 474.240000 0.000000 653.760000 1.100000 ;
      RECT 468.705000 0.000000 473.340000 1.100000 ;
      RECT 467.475000 0.000000 467.805000 1.100000 ;
      RECT 466.245000 0.000000 466.575000 1.100000 ;
      RECT 457.020000 0.000000 465.345000 1.100000 ;
      RECT 453.945000 0.000000 456.120000 1.100000 ;
      RECT 452.100000 0.000000 453.045000 1.100000 ;
      RECT 450.870000 0.000000 451.200000 1.100000 ;
      RECT 449.640000 0.000000 449.970000 1.100000 ;
      RECT 447.180000 0.000000 448.740000 1.100000 ;
      RECT 365.385000 0.000000 446.280000 1.100000 ;
      RECT 327.255000 0.000000 364.485000 1.100000 ;
      RECT 0.000000 0.000000 326.355000 1.100000 ;
    LAYER met5 ;
      RECT 0.000000 438.310000 653.760000 646.760000 ;
      RECT 0.000000 433.510000 649.660000 438.310000 ;
      RECT 0.000000 412.690000 653.760000 433.510000 ;
      RECT 0.000000 407.890000 649.660000 412.690000 ;
      RECT 0.000000 379.750000 653.760000 407.890000 ;
      RECT 0.000000 374.950000 649.660000 379.750000 ;
      RECT 0.000000 372.430000 653.760000 374.950000 ;
      RECT 0.000000 367.630000 649.660000 372.430000 ;
      RECT 0.000000 365.110000 653.760000 367.630000 ;
      RECT 0.000000 360.310000 649.660000 365.110000 ;
      RECT 0.000000 350.470000 653.760000 360.310000 ;
      RECT 4.100000 345.670000 653.760000 350.470000 ;
      RECT 0.000000 339.490000 653.760000 345.670000 ;
      RECT 0.000000 334.690000 649.660000 339.490000 ;
      RECT 0.000000 332.170000 653.760000 334.690000 ;
      RECT 0.000000 327.370000 649.660000 332.170000 ;
      RECT 0.000000 284.590000 653.760000 327.370000 ;
      RECT 0.000000 279.790000 649.660000 284.590000 ;
      RECT 0.000000 273.610000 653.760000 279.790000 ;
      RECT 0.000000 268.810000 649.660000 273.610000 ;
      RECT 0.000000 266.290000 653.760000 268.810000 ;
      RECT 0.000000 261.490000 649.660000 266.290000 ;
      RECT 0.000000 258.970000 653.760000 261.490000 ;
      RECT 0.000000 254.170000 649.660000 258.970000 ;
      RECT 0.000000 251.650000 653.760000 254.170000 ;
      RECT 0.000000 246.850000 649.660000 251.650000 ;
      RECT 0.000000 244.330000 653.760000 246.850000 ;
      RECT 0.000000 239.530000 649.660000 244.330000 ;
      RECT 0.000000 233.350000 653.760000 239.530000 ;
      RECT 0.000000 228.550000 649.660000 233.350000 ;
      RECT 0.000000 226.030000 653.760000 228.550000 ;
      RECT 0.000000 221.230000 649.660000 226.030000 ;
      RECT 0.000000 218.710000 653.760000 221.230000 ;
      RECT 0.000000 213.910000 649.660000 218.710000 ;
      RECT 0.000000 211.390000 653.760000 213.910000 ;
      RECT 0.000000 206.590000 649.660000 211.390000 ;
      RECT 0.000000 200.410000 653.760000 206.590000 ;
      RECT 0.000000 195.610000 649.660000 200.410000 ;
      RECT 0.000000 193.090000 653.760000 195.610000 ;
      RECT 0.000000 188.290000 649.660000 193.090000 ;
      RECT 0.000000 185.770000 653.760000 188.290000 ;
      RECT 0.000000 180.970000 649.660000 185.770000 ;
      RECT 0.000000 178.450000 653.760000 180.970000 ;
      RECT 0.000000 173.650000 649.660000 178.450000 ;
      RECT 0.000000 167.470000 653.760000 173.650000 ;
      RECT 0.000000 162.670000 649.660000 167.470000 ;
      RECT 0.000000 160.150000 653.760000 162.670000 ;
      RECT 0.000000 155.350000 649.660000 160.150000 ;
      RECT 0.000000 152.830000 653.760000 155.350000 ;
      RECT 0.000000 148.030000 649.660000 152.830000 ;
      RECT 0.000000 145.510000 653.760000 148.030000 ;
      RECT 0.000000 140.710000 649.660000 145.510000 ;
      RECT 0.000000 138.190000 653.760000 140.710000 ;
      RECT 0.000000 133.390000 649.660000 138.190000 ;
      RECT 0.000000 0.000000 653.760000 133.390000 ;
  END
END core_macro

END LIBRARY
